VERSION 5.8 ;
BUSBITCHARS "[]" ;
DIVIDERCHAR "/" ;

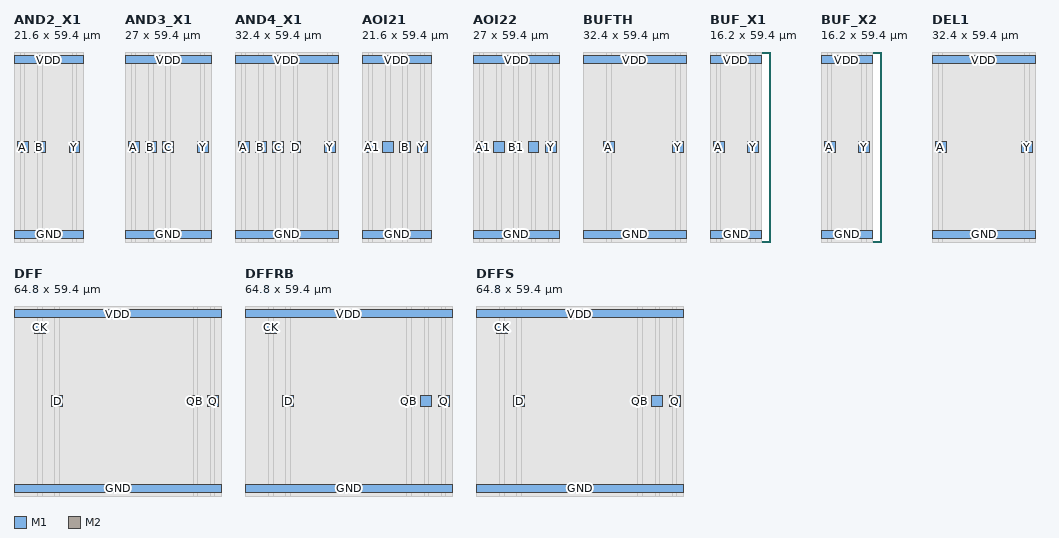
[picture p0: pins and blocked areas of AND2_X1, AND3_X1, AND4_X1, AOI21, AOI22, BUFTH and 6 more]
MACRO AND2_X1
  CLASS CORE ;
  FOREIGN AND2_X1 0 0 ;
  ORIGIN 0 0 ;
  SIZE 21.6 BY 59.4 ;
  SITE TR1UM ;
  SYMMETRY X Y ;
  PIN VDD
    DIRECTION INOUT ;
    USE POWER ;
    PORT
      LAYER M1 ;
        RECT 0 55.7 21.6 58.3 ;
    END
  END VDD
  PIN GND
    DIRECTION INOUT ;
    USE GROUND ;
    PORT
      LAYER M1 ;
        RECT 0 1.1 21.6 3.7 ;
    END
  END GND
  PIN A
    DIRECTION INPUT ;
    USE SIGNAL ;
    PORT
      LAYER M2 ;
        RECT 1 28 4.4 31.4 ;
    END
    PORT
      LAYER M1 ;
        RECT 1 28 4.4 31.4 ;
    END
  END A
  PIN B
    DIRECTION INPUT ;
    USE SIGNAL ;
    PORT
      LAYER M2 ;
        RECT 6.4 28 9.8 31.4 ;
    END
    PORT
      LAYER M1 ;
        RECT 6.4 28 9.8 31.4 ;
    END
  END B
  PIN Y
    DIRECTION OUTPUT ;
    USE SIGNAL ;
    PORT
      LAYER M2 ;
        RECT 17.2 28 20.6 31.4 ;
    END
    PORT
      LAYER M1 ;
        RECT 17.2 28 20.6 31.4 ;
    END
  END Y
  OBS
    LAYER M1 ;
        RECT 0 0 1 59.4 ;
        RECT 1 0 4.4 28 ;
        RECT 1 31.4 4.4 59.4 ;
        RECT 4.4 0 6.4 59.4 ;
        RECT 6.4 0 9.8 28 ;
        RECT 6.4 31.4 9.8 59.4 ;
        RECT 9.8 0 17.2 59.4 ;
        RECT 17.2 0 20.6 28 ;
        RECT 17.2 31.4 20.6 59.4 ;
        RECT 20.6 0 21.6 59.4 ;
    LAYER V1 ;
        RECT 0 0 2 59.4 ;
        RECT 2 0 3.4 29 ;
        RECT 2 30.4 3.4 59.4 ;
        RECT 3.4 0 7.4 59.4 ;
        RECT 7.4 0 8.8 29 ;
        RECT 7.4 30.4 8.8 59.4 ;
        RECT 8.8 0 18.2 59.4 ;
        RECT 18.2 0 19.6 29 ;
        RECT 18.2 30.4 19.6 59.4 ;
        RECT 19.6 0 21.6 59.4 ;
  END
END AND2_X1

MACRO AND3_X1
  CLASS CORE ;
  FOREIGN AND3_X1 0 0 ;
  ORIGIN 0 0 ;
  SIZE 27 BY 59.4 ;
  SITE TR1UM ;
  SYMMETRY X Y ;
  PIN VDD
    DIRECTION INOUT ;
    USE POWER ;
    PORT
      LAYER M1 ;
        RECT 0 55.7 27 58.3 ;
    END
  END VDD
  PIN GND
    DIRECTION INOUT ;
    USE GROUND ;
    PORT
      LAYER M1 ;
        RECT 0 1.1 27 3.7 ;
    END
  END GND
  PIN A
    DIRECTION INPUT ;
    USE SIGNAL ;
    PORT
      LAYER M2 ;
        RECT 1 28 4.4 31.4 ;
    END
    PORT
      LAYER M1 ;
        RECT 1 28 4.4 31.4 ;
    END
  END A
  PIN B
    DIRECTION INPUT ;
    USE SIGNAL ;
    PORT
      LAYER M2 ;
        RECT 6.4 28 9.8 31.4 ;
    END
    PORT
      LAYER M1 ;
        RECT 6.4 28 9.8 31.4 ;
    END
  END B
  PIN C
    DIRECTION INPUT ;
    USE SIGNAL ;
    PORT
      LAYER M2 ;
        RECT 11.8 28 15.2 31.4 ;
    END
    PORT
      LAYER M1 ;
        RECT 11.8 28 15.2 31.4 ;
    END
  END C
  PIN Y
    DIRECTION OUTPUT ;
    USE SIGNAL ;
    PORT
      LAYER M2 ;
        RECT 22.6 28 26 31.4 ;
    END
    PORT
      LAYER M1 ;
        RECT 22.6 28 26 31.4 ;
    END
  END Y
  OBS
    LAYER M1 ;
        RECT 0 0 1 59.4 ;
        RECT 1 0 4.4 28 ;
        RECT 1 31.4 4.4 59.4 ;
        RECT 4.4 0 6.4 59.4 ;
        RECT 6.4 0 9.8 28 ;
        RECT 6.4 31.4 9.8 59.4 ;
        RECT 9.8 0 11.8 59.4 ;
        RECT 11.8 0 15.2 28 ;
        RECT 11.8 31.4 15.2 59.4 ;
        RECT 15.2 0 22.6 59.4 ;
        RECT 22.6 0 26 28 ;
        RECT 22.6 31.4 26 59.4 ;
        RECT 26 0 27 59.4 ;
    LAYER V1 ;
        RECT 0 0 2 59.4 ;
        RECT 2 0 3.4 29 ;
        RECT 2 30.4 3.4 59.4 ;
        RECT 3.4 0 7.4 59.4 ;
        RECT 7.4 0 8.8 29 ;
        RECT 7.4 30.4 8.8 59.4 ;
        RECT 8.8 0 12.8 59.4 ;
        RECT 12.8 0 14.2 29 ;
        RECT 12.8 30.4 14.2 59.4 ;
        RECT 14.2 0 23.6 59.4 ;
        RECT 23.6 0 25 29 ;
        RECT 23.6 30.4 25 59.4 ;
        RECT 25 0 27 59.4 ;
  END
END AND3_X1

MACRO AND4_X1
  CLASS CORE ;
  FOREIGN AND4_X1 0 0 ;
  ORIGIN 0 0 ;
  SIZE 32.4 BY 59.4 ;
  SITE TR1UM ;
  SYMMETRY X Y ;
  PIN VDD
    DIRECTION INOUT ;
    USE POWER ;
    PORT
      LAYER M1 ;
        RECT 0 55.7 32.4 58.3 ;
    END
  END VDD
  PIN GND
    DIRECTION INOUT ;
    USE GROUND ;
    PORT
      LAYER M1 ;
        RECT 0 1.1 32.4 3.7 ;
    END
  END GND
  PIN A
    DIRECTION INPUT ;
    USE SIGNAL ;
    PORT
      LAYER M2 ;
        RECT 1 28 4.4 31.4 ;
    END
    PORT
      LAYER M1 ;
        RECT 1 28 4.4 31.4 ;
    END
  END A
  PIN B
    DIRECTION INPUT ;
    USE SIGNAL ;
    PORT
      LAYER M2 ;
        RECT 6.4 28 9.8 31.4 ;
    END
    PORT
      LAYER M1 ;
        RECT 6.4 28 9.8 31.4 ;
    END
  END B
  PIN C
    DIRECTION INPUT ;
    USE SIGNAL ;
    PORT
      LAYER M2 ;
        RECT 11.8 28 15.2 31.4 ;
    END
    PORT
      LAYER M1 ;
        RECT 11.8 28 15.2 31.4 ;
    END
  END C
  PIN D
    DIRECTION INPUT ;
    USE SIGNAL ;
    PORT
      LAYER M2 ;
        RECT 17.2 28 20.6 31.4 ;
    END
    PORT
      LAYER M1 ;
        RECT 17.2 28 20.6 31.4 ;
    END
  END D
  PIN Y
    DIRECTION OUTPUT ;
    USE SIGNAL ;
    PORT
      LAYER M2 ;
        RECT 28 28 31.4 31.4 ;
    END
    PORT
      LAYER M1 ;
        RECT 28 28 31.4 31.4 ;
    END
  END Y
  OBS
    LAYER M1 ;
        RECT 0 0 1 59.4 ;
        RECT 1 0 4.4 28 ;
        RECT 1 31.4 4.4 59.4 ;
        RECT 4.4 0 6.4 59.4 ;
        RECT 6.4 0 9.8 28 ;
        RECT 6.4 31.4 9.8 59.4 ;
        RECT 9.8 0 11.8 59.4 ;
        RECT 11.8 0 15.2 28 ;
        RECT 11.8 31.4 15.2 59.4 ;
        RECT 15.2 0 17.2 59.4 ;
        RECT 17.2 0 20.6 28 ;
        RECT 17.2 31.4 20.6 59.4 ;
        RECT 20.6 0 28 59.4 ;
        RECT 28 0 31.4 28 ;
        RECT 28 31.4 31.4 59.4 ;
        RECT 31.4 0 32.4 59.4 ;
    LAYER V1 ;
        RECT 0 0 2 59.4 ;
        RECT 2 0 3.4 29 ;
        RECT 2 30.4 3.4 59.4 ;
        RECT 3.4 0 7.4 59.4 ;
        RECT 7.4 0 8.8 29 ;
        RECT 7.4 30.4 8.8 59.4 ;
        RECT 8.8 0 12.8 59.4 ;
        RECT 12.8 0 14.2 29 ;
        RECT 12.8 30.4 14.2 59.4 ;
        RECT 14.2 0 18.2 59.4 ;
        RECT 18.2 0 19.6 29 ;
        RECT 18.2 30.4 19.6 59.4 ;
        RECT 19.6 0 29 59.4 ;
        RECT 29 0 30.4 29 ;
        RECT 29 30.4 30.4 59.4 ;
        RECT 30.4 0 32.4 59.4 ;
  END
END AND4_X1

MACRO AOI21
  CLASS CORE ;
  FOREIGN AOI21 0 0 ;
  ORIGIN 0 0 ;
  SIZE 21.6 BY 59.4 ;
  SITE TR1UM ;
  SYMMETRY X Y ;
  PIN VDD
    DIRECTION INOUT ;
    USE POWER ;
    PORT
      LAYER M1 ;
        RECT 0 55.7 21.6 58.3 ;
    END
  END VDD
  PIN GND
    DIRECTION INOUT ;
    USE GROUND ;
    PORT
      LAYER M1 ;
        RECT 0 1.1 21.6 3.7 ;
    END
  END GND
  PIN A1
    DIRECTION INPUT ;
    USE SIGNAL ;
    PORT
      LAYER M2 ;
        RECT 1 28 4.4 31.4 ;
    END
    PORT
      LAYER M1 ;
        RECT 1 28 4.4 31.4 ;
    END
  END A1
  PIN A2
    DIRECTION INPUT ;
    USE SIGNAL ;
    PORT
      LAYER M2 ;
        RECT 6.4 28 9.8 31.4 ;
    END
    PORT
      LAYER M1 ;
        RECT 6.4 28 9.8 31.4 ;
    END
  END A2
  PIN B
    DIRECTION INPUT ;
    USE SIGNAL ;
    PORT
      LAYER M2 ;
        RECT 11.8 28 15.2 31.4 ;
    END
    PORT
      LAYER M1 ;
        RECT 11.8 28 15.2 31.4 ;
    END
  END B
  PIN Y
    DIRECTION OUTPUT ;
    USE SIGNAL ;
    PORT
      LAYER M2 ;
        RECT 17.2 28 20.6 31.4 ;
    END
    PORT
      LAYER M1 ;
        RECT 17.2 28 20.6 31.4 ;
    END
  END Y
  OBS
    LAYER M1 ;
        RECT 0 0 1 59.4 ;
        RECT 1 0 4.4 28 ;
        RECT 1 31.4 4.4 59.4 ;
        RECT 4.4 0 6.4 59.4 ;
        RECT 6.4 0 9.8 28 ;
        RECT 6.4 31.4 9.8 59.4 ;
        RECT 9.8 0 11.8 59.4 ;
        RECT 11.8 0 15.2 28 ;
        RECT 11.8 31.4 15.2 59.4 ;
        RECT 15.2 0 17.2 59.4 ;
        RECT 17.2 0 20.6 28 ;
        RECT 17.2 31.4 20.6 59.4 ;
        RECT 20.6 0 21.6 59.4 ;
    LAYER V1 ;
        RECT 0 0 2 59.4 ;
        RECT 2 0 3.4 29 ;
        RECT 2 30.4 3.4 59.4 ;
        RECT 3.4 0 7.4 59.4 ;
        RECT 7.4 0 8.8 29 ;
        RECT 7.4 30.4 8.8 59.4 ;
        RECT 8.8 0 12.8 59.4 ;
        RECT 12.8 0 14.2 29 ;
        RECT 12.8 30.4 14.2 59.4 ;
        RECT 14.2 0 18.2 59.4 ;
        RECT 18.2 0 19.6 29 ;
        RECT 18.2 30.4 19.6 59.4 ;
        RECT 19.6 0 21.6 59.4 ;
  END
END AOI21

MACRO AOI22
  CLASS CORE ;
  FOREIGN AOI22 0 0 ;
  ORIGIN 0 0 ;
  SIZE 27 BY 59.4 ;
  SITE TR1UM ;
  SYMMETRY X Y ;
  PIN VDD
    DIRECTION INOUT ;
    USE POWER ;
    PORT
      LAYER M1 ;
        RECT 0 55.7 27 58.3 ;
    END
  END VDD
  PIN GND
    DIRECTION INOUT ;
    USE GROUND ;
    PORT
      LAYER M1 ;
        RECT 0 1.1 27 3.7 ;
    END
  END GND
  PIN A1
    DIRECTION INPUT ;
    USE SIGNAL ;
    PORT
      LAYER M2 ;
        RECT 1 28 4.4 31.4 ;
    END
    PORT
      LAYER M1 ;
        RECT 1 28 4.4 31.4 ;
    END
  END A1
  PIN A2
    DIRECTION INPUT ;
    USE SIGNAL ;
    PORT
      LAYER M2 ;
        RECT 6.4 28 9.8 31.4 ;
    END
    PORT
      LAYER M1 ;
        RECT 6.4 28 9.8 31.4 ;
    END
  END A2
  PIN B1
    DIRECTION INPUT ;
    USE SIGNAL ;
    PORT
      LAYER M2 ;
        RECT 11.8 28 15.2 31.4 ;
    END
    PORT
      LAYER M1 ;
        RECT 11.8 28 15.2 31.4 ;
    END
  END B1
  PIN B2
    DIRECTION INPUT ;
    USE SIGNAL ;
    PORT
      LAYER M2 ;
        RECT 17.2 28 20.6 31.4 ;
    END
    PORT
      LAYER M1 ;
        RECT 17.2 28 20.6 31.4 ;
    END
  END B2
  PIN Y
    DIRECTION OUTPUT ;
    USE SIGNAL ;
    PORT
      LAYER M2 ;
        RECT 22.6 28 26 31.4 ;
    END
    PORT
      LAYER M1 ;
        RECT 22.6 28 26 31.4 ;
    END
  END Y
  OBS
    LAYER M1 ;
        RECT 0 0 1 59.4 ;
        RECT 1 0 4.4 28 ;
        RECT 1 31.4 4.4 59.4 ;
        RECT 4.4 0 6.4 59.4 ;
        RECT 6.4 0 9.8 28 ;
        RECT 6.4 31.4 9.8 59.4 ;
        RECT 9.8 0 11.8 59.4 ;
        RECT 11.8 0 15.2 28 ;
        RECT 11.8 31.4 15.2 59.4 ;
        RECT 15.2 0 17.2 59.4 ;
        RECT 17.2 0 20.6 28 ;
        RECT 17.2 31.4 20.6 59.4 ;
        RECT 20.6 0 22.6 59.4 ;
        RECT 22.6 0 26 28 ;
        RECT 22.6 31.4 26 59.4 ;
        RECT 26 0 27 59.4 ;
    LAYER V1 ;
        RECT 0 0 2 59.4 ;
        RECT 2 0 3.4 29 ;
        RECT 2 30.4 3.4 59.4 ;
        RECT 3.4 0 7.4 59.4 ;
        RECT 7.4 0 8.8 29 ;
        RECT 7.4 30.4 8.8 59.4 ;
        RECT 8.8 0 12.8 59.4 ;
        RECT 12.8 0 14.2 29 ;
        RECT 12.8 30.4 14.2 59.4 ;
        RECT 14.2 0 18.2 59.4 ;
        RECT 18.2 0 19.6 29 ;
        RECT 18.2 30.4 19.6 59.4 ;
        RECT 19.6 0 23.6 59.4 ;
        RECT 23.6 0 25 29 ;
        RECT 23.6 30.4 25 59.4 ;
        RECT 25 0 27 59.4 ;
  END
END AOI22

MACRO BUFTH
  CLASS CORE ;
  FOREIGN BUFTH 0 0 ;
  ORIGIN 0 0 ;
  SIZE 32.4 BY 59.4 ;
  SITE TR1UM ;
  SYMMETRY X Y ;
  PIN VDD
    DIRECTION INOUT ;
    USE POWER ;
    PORT
      LAYER M1 ;
        RECT 0 55.7 32.4 58.3 ;
    END
  END VDD
  PIN GND
    DIRECTION INOUT ;
    USE GROUND ;
    PORT
      LAYER M1 ;
        RECT 0 1.1 32.4 3.7 ;
    END
  END GND
  PIN A
    DIRECTION INPUT ;
    USE SIGNAL ;
    PORT
      LAYER M2 ;
        RECT 6.4 28 9.8 31.4 ;
    END
    PORT
      LAYER M1 ;
        RECT 6.4 28 9.8 31.4 ;
    END
  END A
  PIN Y
    DIRECTION OUTPUT ;
    USE SIGNAL ;
    PORT
      LAYER M2 ;
        RECT 28 28 31.4 31.4 ;
    END
    PORT
      LAYER M1 ;
        RECT 28 28 31.4 31.4 ;
    END
  END Y
  OBS
    LAYER M1 ;
        RECT 0 0 6.4 59.4 ;
        RECT 6.4 0 9.8 28 ;
        RECT 6.4 31.4 9.8 59.4 ;
        RECT 9.8 0 28 59.4 ;
        RECT 28 0 31.4 28 ;
        RECT 28 31.4 31.4 59.4 ;
        RECT 31.4 0 32.4 59.4 ;
    LAYER V1 ;
        RECT 0 0 7.4 59.4 ;
        RECT 7.4 0 8.8 29 ;
        RECT 7.4 30.4 8.8 59.4 ;
        RECT 8.8 0 29 59.4 ;
        RECT 29 0 30.4 29 ;
        RECT 29 30.4 30.4 59.4 ;
        RECT 30.4 0 32.4 59.4 ;
  END
END BUFTH

MACRO BUF_X1
  CLASS CORE ;
  FOREIGN BUF_X1 0 0 ;
  ORIGIN 0 0 ;
  SIZE 16.2 BY 59.4 ;
  SITE TR1UM ;
  SYMMETRY X Y ;
  PIN VDD
    DIRECTION INOUT ;
    USE POWER ;
    PORT
      LAYER M1 ;
        RECT 0 55.7 16.2 58.3 ;
    END
  END VDD
  PIN GND
    DIRECTION INOUT ;
    USE GROUND ;
    PORT
      LAYER M1 ;
        RECT 0 1.1 16.2 3.7 ;
    END
  END GND
  PIN A
    DIRECTION INPUT ;
    USE SIGNAL ;
    PORT
      LAYER M2 ;
        RECT 1 28 4.4 31.4 ;
    END
    PORT
      LAYER M1 ;
        RECT 1 28 4.4 31.4 ;
    END
  END A
  PIN Y
    DIRECTION OUTPUT ;
    USE SIGNAL ;
    PORT
      LAYER M2 ;
        RECT 11.8 28 15.2 31.4 ;
    END
    PORT
      LAYER M1 ;
        RECT 11.8 28 15.2 31.4 ;
    END
  END Y
  OBS
    LAYER M1 ;
        RECT 0 0 1 59.4 ;
        RECT 1 0 4.4 28 ;
        RECT 1 31.4 4.4 59.4 ;
        RECT 4.4 0 11.8 59.4 ;
        RECT 11.8 0 15.2 28 ;
        RECT 11.8 31.4 15.2 59.4 ;
        RECT 15.2 0 16.2 59.4 ;
    LAYER V1 ;
        RECT 0 0 2 59.4 ;
        RECT 2 0 3.4 29 ;
        RECT 2 30.4 3.4 59.4 ;
        RECT 3.4 0 12.8 59.4 ;
        RECT 12.8 0 14.2 29 ;
        RECT 12.8 30.4 14.2 59.4 ;
        RECT 14.2 0 16.2 59.4 ;
  END
END BUF_X1

MACRO BUF_X2
  CLASS CORE ;
  FOREIGN BUF_X2 0 0 ;
  ORIGIN 0 0 ;
  SIZE 16.2 BY 59.4 ;
  SITE TR1UM ;
  SYMMETRY X Y ;
  PIN VDD
    DIRECTION INOUT ;
    USE POWER ;
    PORT
      LAYER M1 ;
        RECT 0 55.7 16.2 58.3 ;
    END
  END VDD
  PIN GND
    DIRECTION INOUT ;
    USE GROUND ;
    PORT
      LAYER M1 ;
        RECT 0 1.1 16.2 3.7 ;
    END
  END GND
  PIN A
    DIRECTION INPUT ;
    USE SIGNAL ;
    PORT
      LAYER M2 ;
        RECT 1 28 4.4 31.4 ;
    END
    PORT
      LAYER M1 ;
        RECT 1 28 4.4 31.4 ;
    END
  END A
  PIN Y
    DIRECTION OUTPUT ;
    USE SIGNAL ;
    PORT
      LAYER M2 ;
        RECT 11.8 28 15.2 31.4 ;
    END
    PORT
      LAYER M1 ;
        RECT 11.8 28 15.2 31.4 ;
    END
  END Y
  OBS
    LAYER M1 ;
        RECT 0 0 1 59.4 ;
        RECT 1 0 4.4 28 ;
        RECT 1 31.4 4.4 59.4 ;
        RECT 4.4 0 11.8 59.4 ;
        RECT 11.8 0 15.2 28 ;
        RECT 11.8 31.4 15.2 59.4 ;
        RECT 15.2 0 16.2 59.4 ;
    LAYER V1 ;
        RECT 0 0 2 59.4 ;
        RECT 2 0 3.4 29 ;
        RECT 2 30.4 3.4 59.4 ;
        RECT 3.4 0 12.8 59.4 ;
        RECT 12.8 0 14.2 29 ;
        RECT 12.8 30.4 14.2 59.4 ;
        RECT 14.2 0 16.2 59.4 ;
  END
END BUF_X2

MACRO DEL1
  CLASS CORE ;
  FOREIGN DEL1 0 0 ;
  ORIGIN 0 0 ;
  SIZE 32.4 BY 59.4 ;
  SITE TR1UM ;
  SYMMETRY X Y ;
  PIN VDD
    DIRECTION INOUT ;
    USE POWER ;
    PORT
      LAYER M1 ;
        RECT 0 55.7 32.4 58.3 ;
    END
  END VDD
  PIN GND
    DIRECTION INOUT ;
    USE GROUND ;
    PORT
      LAYER M1 ;
        RECT 0 1.1 32.4 3.7 ;
    END
  END GND
  PIN A
    DIRECTION INPUT ;
    USE SIGNAL ;
    PORT
      LAYER M2 ;
        RECT 1 28 4.4 31.4 ;
    END
    PORT
      LAYER M1 ;
        RECT 1 28 4.4 31.4 ;
    END
  END A
  PIN Y
    DIRECTION OUTPUT ;
    USE SIGNAL ;
    PORT
      LAYER M2 ;
        RECT 28 28 31.4 31.4 ;
    END
    PORT
      LAYER M1 ;
        RECT 28 28 31.4 31.4 ;
    END
  END Y
  OBS
    LAYER M1 ;
        RECT 0 0 1 59.4 ;
        RECT 1 0 4.4 28 ;
        RECT 1 31.4 4.4 59.4 ;
        RECT 4.4 0 28 59.4 ;
        RECT 28 0 31.4 28 ;
        RECT 28 31.4 31.4 59.4 ;
        RECT 31.4 0 32.4 59.4 ;
    LAYER V1 ;
        RECT 0 0 2 59.4 ;
        RECT 2 0 3.4 29 ;
        RECT 2 30.4 3.4 59.4 ;
        RECT 3.4 0 29 59.4 ;
        RECT 29 0 30.4 29 ;
        RECT 29 30.4 30.4 59.4 ;
        RECT 30.4 0 32.4 59.4 ;
  END
END DEL1

MACRO DFF
  CLASS CORE ;
  FOREIGN DFF 0 0 ;
  ORIGIN 0 0 ;
  SIZE 64.8 BY 59.4 ;
  SITE TR1UM ;
  SYMMETRY X Y ;
  PIN VDD
    DIRECTION INOUT ;
    USE POWER ;
    PORT
      LAYER M1 ;
        RECT 0 55.7 64.8 58.3 ;
    END
  END VDD
  PIN GND
    DIRECTION INOUT ;
    USE GROUND ;
    PORT
      LAYER M1 ;
        RECT 0 1.1 64.8 3.7 ;
    END
  END GND
  PIN CK
    DIRECTION INPUT ;
    USE SIGNAL ;
    PORT
      LAYER M2 ;
        RECT 6.4 50.9 9.8 54.3 ;
    END
    PORT
      LAYER M1 ;
        RECT 6.4 50.9 9.8 54.3 ;
    END
  END CK
  PIN D
    DIRECTION INPUT ;
    USE SIGNAL ;
    PORT
      LAYER M2 ;
        RECT 11.8 27.9 15.2 31.3 ;
    END
    PORT
      LAYER M1 ;
        RECT 11.8 27.9 15.2 31.3 ;
    END
  END D
  PIN Q
    DIRECTION OUTPUT ;
    USE SIGNAL ;
    PORT
      LAYER M2 ;
        RECT 60.4 27.9 63.8 31.3 ;
    END
    PORT
      LAYER M1 ;
        RECT 60.4 27.9 63.8 31.3 ;
    END
  END Q
  PIN QB
    DIRECTION OUTPUT ;
    USE SIGNAL ;
    PORT
      LAYER M2 ;
        RECT 55 27.9 58.4 31.3 ;
    END
    PORT
      LAYER M1 ;
        RECT 55 27.9 58.4 31.3 ;
    END
  END QB
  OBS
    LAYER M1 ;
        RECT 0 0 6.4 59.4 ;
        RECT 6.4 0 9.8 50.9 ;
        RECT 6.4 54.3 9.8 59.4 ;
        RECT 9.8 0 11.8 59.4 ;
        RECT 11.8 0 15.2 27.9 ;
        RECT 11.8 31.3 15.2 59.4 ;
        RECT 15.2 0 55 59.4 ;
        RECT 55 0 58.4 27.9 ;
        RECT 55 31.3 58.4 59.4 ;
        RECT 58.4 0 60.4 59.4 ;
        RECT 60.4 0 63.8 27.9 ;
        RECT 60.4 31.3 63.8 59.4 ;
        RECT 63.8 0 64.8 59.4 ;
    LAYER V1 ;
        RECT 0 0 7.4 59.4 ;
        RECT 7.4 0 8.8 51.9 ;
        RECT 7.4 53.3 8.8 59.4 ;
        RECT 8.8 0 12.8 59.4 ;
        RECT 12.8 0 14.2 28.9 ;
        RECT 12.8 30.3 14.2 59.4 ;
        RECT 14.2 0 56 59.4 ;
        RECT 56 0 57.4 28.9 ;
        RECT 56 30.3 57.4 59.4 ;
        RECT 57.4 0 61.4 59.4 ;
        RECT 61.4 0 62.8 28.9 ;
        RECT 61.4 30.3 62.8 59.4 ;
        RECT 62.8 0 64.8 59.4 ;
  END
END DFF

MACRO DFFRB
  CLASS CORE ;
  FOREIGN DFFRB 0 0 ;
  ORIGIN 0 0 ;
  SIZE 64.8 BY 59.4 ;
  SITE TR1UM ;
  SYMMETRY X Y ;
  PIN VDD
    DIRECTION INOUT ;
    USE POWER ;
    PORT
      LAYER M1 ;
        RECT 0 55.7 64.8 58.3 ;
    END
  END VDD
  PIN GND
    DIRECTION INOUT ;
    USE GROUND ;
    PORT
      LAYER M1 ;
        RECT 0 1.1 64.8 3.7 ;
    END
  END GND
  PIN CK
    DIRECTION INPUT ;
    USE SIGNAL ;
    PORT
      LAYER M2 ;
        RECT 6.4 50.9 9.8 54.3 ;
    END
    PORT
      LAYER M1 ;
        RECT 6.4 50.9 9.8 54.3 ;
    END
  END CK
  PIN D
    DIRECTION INPUT ;
    USE SIGNAL ;
    PORT
      LAYER M2 ;
        RECT 11.8 27.9 15.2 31.3 ;
    END
    PORT
      LAYER M1 ;
        RECT 11.8 27.9 15.2 31.3 ;
    END
  END D
  PIN Q
    DIRECTION OUTPUT ;
    USE SIGNAL ;
    PORT
      LAYER M2 ;
        RECT 60.4 27.9 63.8 31.3 ;
    END
    PORT
      LAYER M1 ;
        RECT 60.4 27.9 63.8 31.3 ;
    END
  END Q
  PIN QB
    DIRECTION OUTPUT ;
    USE SIGNAL ;
    PORT
      LAYER M2 ;
        RECT 49.6 27.9 53 31.3 ;
        RECT 49.6 27.9 53 31.3 ;
    END
    PORT
      LAYER M1 ;
        RECT 49.6 27.9 53 31.3 ;
        RECT 49.6 27.9 53 31.3 ;
    END
  END QB
  PIN RSTB
    DIRECTION INPUT ;
    USE SIGNAL ;
    PORT
      LAYER M2 ;
        RECT 55 27.9 58.4 31.3 ;
    END
    PORT
      LAYER M1 ;
        RECT 55 27.9 58.4 31.3 ;
    END
  END RSTB
  OBS
    LAYER M1 ;
        RECT 0 0 6.4 59.4 ;
        RECT 6.4 0 9.8 50.9 ;
        RECT 6.4 54.3 9.8 59.4 ;
        RECT 9.8 0 11.8 59.4 ;
        RECT 11.8 0 15.2 27.9 ;
        RECT 11.8 31.3 15.2 59.4 ;
        RECT 15.2 0 49.6 59.4 ;
        RECT 49.6 0 53 27.9 ;
        RECT 49.6 31.3 53 59.4 ;
        RECT 53 0 55 59.4 ;
        RECT 55 0 58.4 27.9 ;
        RECT 55 31.3 58.4 59.4 ;
        RECT 58.4 0 60.4 59.4 ;
        RECT 60.4 0 63.8 27.9 ;
        RECT 60.4 31.3 63.8 59.4 ;
        RECT 63.8 0 64.8 59.4 ;
    LAYER V1 ;
        RECT 0 0 7.4 59.4 ;
        RECT 7.4 0 8.8 51.9 ;
        RECT 7.4 53.3 8.8 59.4 ;
        RECT 8.8 0 12.8 59.4 ;
        RECT 12.8 0 14.2 28.9 ;
        RECT 12.8 30.3 14.2 59.4 ;
        RECT 14.2 0 50.6 59.4 ;
        RECT 50.6 0 52 28.9 ;
        RECT 50.6 30.3 52 59.4 ;
        RECT 52 0 56 59.4 ;
        RECT 56 0 57.4 28.9 ;
        RECT 56 30.3 57.4 59.4 ;
        RECT 57.4 0 61.4 59.4 ;
        RECT 61.4 0 62.8 28.9 ;
        RECT 61.4 30.3 62.8 59.4 ;
        RECT 62.8 0 64.8 59.4 ;
  END
END DFFRB

MACRO DFFS
  CLASS CORE ;
  FOREIGN DFFS 0 0 ;
  ORIGIN 0 0 ;
  SIZE 64.8 BY 59.4 ;
  SITE TR1UM ;
  SYMMETRY X Y ;
  PIN VDD
    DIRECTION INOUT ;
    USE POWER ;
    PORT
      LAYER M1 ;
        RECT 0 55.7 64.8 58.3 ;
    END
  END VDD
  PIN GND
    DIRECTION INOUT ;
    USE GROUND ;
    PORT
      LAYER M1 ;
        RECT 0 1.1 64.8 3.7 ;
    END
  END GND
  PIN CK
    DIRECTION INPUT ;
    USE SIGNAL ;
    PORT
      LAYER M2 ;
        RECT 6.4 50.9 9.8 54.3 ;
    END
    PORT
      LAYER M1 ;
        RECT 6.4 50.9 9.8 54.3 ;
    END
  END CK
  PIN D
    DIRECTION INPUT ;
    USE SIGNAL ;
    PORT
      LAYER M2 ;
        RECT 11.8 27.9 15.2 31.3 ;
    END
    PORT
      LAYER M1 ;
        RECT 11.8 27.9 15.2 31.3 ;
    END
  END D
  PIN Q
    DIRECTION OUTPUT ;
    USE SIGNAL ;
    PORT
      LAYER M2 ;
        RECT 60.4 27.9 63.8 31.3 ;
    END
    PORT
      LAYER M1 ;
        RECT 60.4 27.9 63.8 31.3 ;
    END
  END Q
  PIN QB
    DIRECTION OUTPUT ;
    USE SIGNAL ;
    PORT
      LAYER M2 ;
        RECT 49.6 27.9 53 31.3 ;
        RECT 49.6 27.9 53 31.3 ;
    END
    PORT
      LAYER M1 ;
        RECT 49.6 27.9 53 31.3 ;
        RECT 49.6 27.9 53 31.3 ;
    END
  END QB
  PIN SET
    DIRECTION INPUT ;
    USE SIGNAL ;
    PORT
      LAYER M2 ;
        RECT 55 27.9 58.4 31.3 ;
    END
    PORT
      LAYER M1 ;
        RECT 55 27.9 58.4 31.3 ;
    END
  END SET
  OBS
    LAYER M1 ;
        RECT 0 0 6.4 59.4 ;
        RECT 6.4 0 9.8 50.9 ;
        RECT 6.4 54.3 9.8 59.4 ;
        RECT 9.8 0 11.8 59.4 ;
        RECT 11.8 0 15.2 27.9 ;
        RECT 11.8 31.3 15.2 59.4 ;
        RECT 15.2 0 49.6 59.4 ;
        RECT 49.6 0 53 27.9 ;
        RECT 49.6 31.3 53 59.4 ;
        RECT 53 0 55 59.4 ;
        RECT 55 0 58.4 27.9 ;
        RECT 55 31.3 58.4 59.4 ;
        RECT 58.4 0 60.4 59.4 ;
        RECT 60.4 0 63.8 27.9 ;
        RECT 60.4 31.3 63.8 59.4 ;
        RECT 63.8 0 64.8 59.4 ;
    LAYER V1 ;
        RECT 0 0 7.4 59.4 ;
        RECT 7.4 0 8.8 51.9 ;
        RECT 7.4 53.3 8.8 59.4 ;
        RECT 8.8 0 12.8 59.4 ;
        RECT 12.8 0 14.2 28.9 ;
        RECT 12.8 30.3 14.2 59.4 ;
        RECT 14.2 0 50.6 59.4 ;
        RECT 50.6 0 52 28.9 ;
        RECT 50.6 30.3 52 59.4 ;
        RECT 52 0 56 59.4 ;
        RECT 56 0 57.4 28.9 ;
        RECT 56 30.3 57.4 59.4 ;
        RECT 57.4 0 61.4 59.4 ;
        RECT 61.4 0 62.8 28.9 ;
        RECT 61.4 30.3 62.8 59.4 ;
        RECT 62.8 0 64.8 59.4 ;
  END
END DFFS

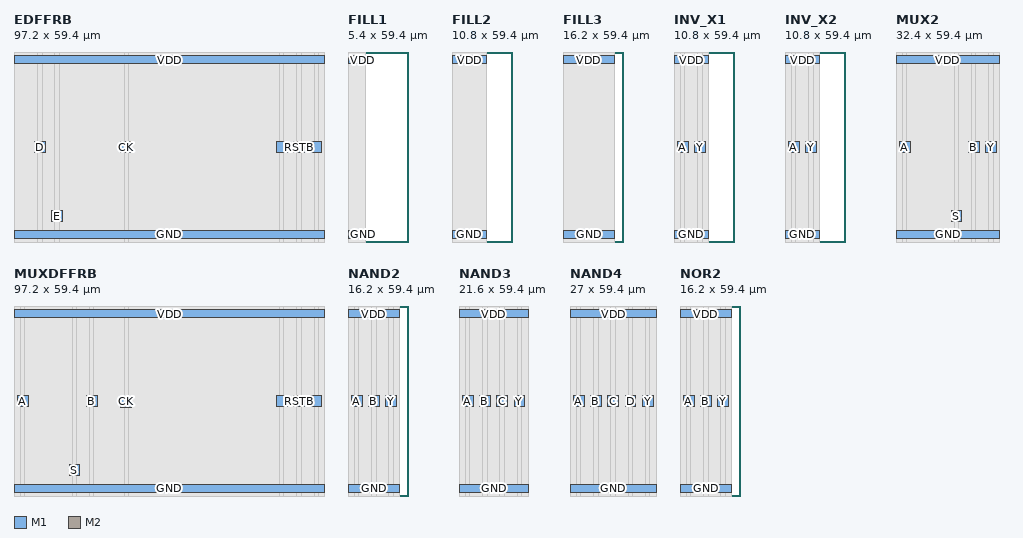
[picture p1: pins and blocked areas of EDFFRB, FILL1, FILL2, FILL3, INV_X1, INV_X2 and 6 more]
MACRO EDFFRB
  CLASS CORE ;
  FOREIGN EDFFRB 0 0 ;
  ORIGIN 0 0 ;
  SIZE 97.2 BY 59.4 ;
  SITE TR1UM ;
  SYMMETRY X Y ;
  PIN VDD
    DIRECTION INOUT ;
    USE POWER ;
    PORT
      LAYER M1 ;
        RECT 0 55.7 97.2 58.3 ;
    END
  END VDD
  PIN GND
    DIRECTION INOUT ;
    USE GROUND ;
    PORT
      LAYER M1 ;
        RECT 0 1.1 97.2 3.7 ;
    END
  END GND
  PIN CK
    DIRECTION INPUT ;
    USE SIGNAL ;
    PORT
      LAYER M2 ;
        RECT 33.4 27.9 36.8 31.3 ;
    END
    PORT
      LAYER M1 ;
        RECT 33.4 27.9 36.8 31.3 ;
    END
  END CK
  PIN D
    DIRECTION INPUT ;
    USE SIGNAL ;
    PORT
      LAYER M2 ;
        RECT 6.4 27.9 9.8 31.3 ;
    END
    PORT
      LAYER M1 ;
        RECT 6.4 27.9 9.8 31.3 ;
    END
  END D
  PIN E
    DIRECTION INPUT ;
    USE SIGNAL ;
    PORT
      LAYER M2 ;
        RECT 11.8 6.3 15.2 9.7 ;
    END
    PORT
      LAYER M1 ;
        RECT 11.8 6.3 15.2 9.7 ;
    END
  END E
  PIN Q
    DIRECTION OUTPUT ;
    USE SIGNAL ;
    PORT
      LAYER M2 ;
        RECT 92.8 27.9 96.2 31.3 ;
    END
    PORT
      LAYER M1 ;
        RECT 92.8 27.9 96.2 31.3 ;
    END
  END Q
  PIN QB
    DIRECTION OUTPUT ;
    USE SIGNAL ;
    PORT
      LAYER M2 ;
        RECT 82 27.9 85.4 31.3 ;
        RECT 82 27.9 85.4 31.3 ;
    END
    PORT
      LAYER M1 ;
        RECT 82 27.9 85.4 31.3 ;
        RECT 82 27.9 85.4 31.3 ;
    END
  END QB
  PIN RSTB
    DIRECTION INPUT ;
    USE SIGNAL ;
    PORT
      LAYER M2 ;
        RECT 87.4 27.9 90.8 31.3 ;
    END
    PORT
      LAYER M1 ;
        RECT 87.4 27.9 90.8 31.3 ;
    END
  END RSTB
  OBS
    LAYER M1 ;
        RECT 0 0 6.4 59.4 ;
        RECT 6.4 0 9.8 27.9 ;
        RECT 6.4 31.3 9.8 59.4 ;
        RECT 9.8 0 11.8 59.4 ;
        RECT 11.8 0 15.2 6.3 ;
        RECT 11.8 9.7 15.2 59.4 ;
        RECT 15.2 0 33.4 59.4 ;
        RECT 33.4 0 36.8 27.9 ;
        RECT 33.4 31.3 36.8 59.4 ;
        RECT 36.8 0 82 59.4 ;
        RECT 82 0 85.4 27.9 ;
        RECT 82 31.3 85.4 59.4 ;
        RECT 85.4 0 87.4 59.4 ;
        RECT 87.4 0 90.8 27.9 ;
        RECT 87.4 31.3 90.8 59.4 ;
        RECT 90.8 0 92.8 59.4 ;
        RECT 92.8 0 96.2 27.9 ;
        RECT 92.8 31.3 96.2 59.4 ;
        RECT 96.2 0 97.2 59.4 ;
    LAYER V1 ;
        RECT 0 0 7.4 59.4 ;
        RECT 7.4 0 8.8 28.9 ;
        RECT 7.4 30.3 8.8 59.4 ;
        RECT 8.8 0 12.8 59.4 ;
        RECT 12.8 0 14.2 7.3 ;
        RECT 12.8 8.7 14.2 59.4 ;
        RECT 14.2 0 34.4 59.4 ;
        RECT 34.4 0 35.8 28.9 ;
        RECT 34.4 30.3 35.8 59.4 ;
        RECT 35.8 0 83 59.4 ;
        RECT 83 0 84.4 28.9 ;
        RECT 83 30.3 84.4 59.4 ;
        RECT 84.4 0 88.4 59.4 ;
        RECT 88.4 0 89.8 28.9 ;
        RECT 88.4 30.3 89.8 59.4 ;
        RECT 89.8 0 93.8 59.4 ;
        RECT 93.8 0 95.2 28.9 ;
        RECT 93.8 30.3 95.2 59.4 ;
        RECT 95.2 0 97.2 59.4 ;
  END
END EDFFRB

MACRO FILL1
  CLASS CORE SPACER ;
  FOREIGN FILL1 0 0 ;
  ORIGIN 0 0 ;
  SIZE 5.4 BY 59.4 ;
  SITE TR1UM ;
  SYMMETRY X Y ;
  PIN VDD
    DIRECTION INOUT ;
    USE POWER ;
    PORT
      LAYER M1 ;
        RECT 0 55.7 5.4 58.3 ;
    END
  END VDD
  PIN GND
    DIRECTION INOUT ;
    USE GROUND ;
    PORT
      LAYER M1 ;
        RECT 0 1.1 5.4 3.7 ;
    END
  END GND
  OBS
    LAYER M1 ;
        RECT 0 0 5.4 59.4 ;
    LAYER V1 ;
        RECT 0 0 5.4 59.4 ;
  END
END FILL1

MACRO FILL2
  CLASS CORE SPACER ;
  FOREIGN FILL2 0 0 ;
  ORIGIN 0 0 ;
  SIZE 10.8 BY 59.4 ;
  SITE TR1UM ;
  SYMMETRY X Y ;
  PIN VDD
    DIRECTION INOUT ;
    USE POWER ;
    PORT
      LAYER M1 ;
        RECT 0 55.7 10.8 58.3 ;
    END
  END VDD
  PIN GND
    DIRECTION INOUT ;
    USE GROUND ;
    PORT
      LAYER M1 ;
        RECT 0 1.1 10.8 3.7 ;
    END
  END GND
  OBS
    LAYER M1 ;
        RECT 0 0 10.8 59.4 ;
    LAYER V1 ;
        RECT 0 0 10.8 59.4 ;
  END
END FILL2

MACRO FILL3
  CLASS CORE SPACER ;
  FOREIGN FILL3 0 0 ;
  ORIGIN 0 0 ;
  SIZE 16.2 BY 59.4 ;
  SITE TR1UM ;
  SYMMETRY X Y ;
  PIN VDD
    DIRECTION INOUT ;
    USE POWER ;
    PORT
      LAYER M1 ;
        RECT 0 55.7 16.2 58.3 ;
    END
  END VDD
  PIN GND
    DIRECTION INOUT ;
    USE GROUND ;
    PORT
      LAYER M1 ;
        RECT 0 1.1 16.2 3.7 ;
    END
  END GND
  OBS
    LAYER M1 ;
        RECT 0 0 16.2 59.4 ;
    LAYER V1 ;
        RECT 0 0 16.2 59.4 ;
  END
END FILL3

MACRO INV_X1
  CLASS CORE ;
  FOREIGN INV_X1 0 0 ;
  ORIGIN 0 0 ;
  SIZE 10.8 BY 59.4 ;
  SITE TR1UM ;
  SYMMETRY X Y ;
  PIN VDD
    DIRECTION INOUT ;
    USE POWER ;
    PORT
      LAYER M1 ;
        RECT 0 55.7 10.8 58.3 ;
    END
  END VDD
  PIN GND
    DIRECTION INOUT ;
    USE GROUND ;
    PORT
      LAYER M1 ;
        RECT 0 1.1 10.8 3.7 ;
    END
  END GND
  PIN A
    DIRECTION INPUT ;
    USE SIGNAL ;
    PORT
      LAYER M2 ;
        RECT 1 28 4.4 31.4 ;
    END
    PORT
      LAYER M1 ;
        RECT 1 28 4.4 31.4 ;
    END
  END A
  PIN Y
    DIRECTION OUTPUT ;
    USE SIGNAL ;
    PORT
      LAYER M2 ;
        RECT 6.4 28 9.8 31.4 ;
    END
    PORT
      LAYER M1 ;
        RECT 6.4 28 9.8 31.4 ;
    END
  END Y
  OBS
    LAYER M1 ;
        RECT 0 0 1 59.4 ;
        RECT 1 0 4.4 28 ;
        RECT 1 31.4 4.4 59.4 ;
        RECT 4.4 0 6.4 59.4 ;
        RECT 6.4 0 9.8 28 ;
        RECT 6.4 31.4 9.8 59.4 ;
        RECT 9.8 0 10.8 59.4 ;
    LAYER V1 ;
        RECT 0 0 2 59.4 ;
        RECT 2 0 3.4 29 ;
        RECT 2 30.4 3.4 59.4 ;
        RECT 3.4 0 7.4 59.4 ;
        RECT 7.4 0 8.8 29 ;
        RECT 7.4 30.4 8.8 59.4 ;
        RECT 8.8 0 10.8 59.4 ;
  END
END INV_X1

MACRO INV_X2
  CLASS CORE ;
  FOREIGN INV_X2 0 0 ;
  ORIGIN 0 0 ;
  SIZE 10.8 BY 59.4 ;
  SITE TR1UM ;
  SYMMETRY X Y ;
  PIN VDD
    DIRECTION INOUT ;
    USE POWER ;
    PORT
      LAYER M1 ;
        RECT 0 55.7 10.8 58.3 ;
    END
  END VDD
  PIN GND
    DIRECTION INOUT ;
    USE GROUND ;
    PORT
      LAYER M1 ;
        RECT 0 1.1 10.8 3.7 ;
    END
  END GND
  PIN A
    DIRECTION INPUT ;
    USE SIGNAL ;
    PORT
      LAYER M2 ;
        RECT 1 28 4.4 31.4 ;
    END
    PORT
      LAYER M1 ;
        RECT 1 28 4.4 31.4 ;
    END
  END A
  PIN Y
    DIRECTION OUTPUT ;
    USE SIGNAL ;
    PORT
      LAYER M2 ;
        RECT 6.4 28 9.8 31.4 ;
    END
    PORT
      LAYER M1 ;
        RECT 6.4 28 9.8 31.4 ;
    END
  END Y
  OBS
    LAYER M1 ;
        RECT 0 0 1 59.4 ;
        RECT 1 0 4.4 28 ;
        RECT 1 31.4 4.4 59.4 ;
        RECT 4.4 0 6.4 59.4 ;
        RECT 6.4 0 9.8 28 ;
        RECT 6.4 31.4 9.8 59.4 ;
        RECT 9.8 0 10.8 59.4 ;
    LAYER V1 ;
        RECT 0 0 2 59.4 ;
        RECT 2 0 3.4 29 ;
        RECT 2 30.4 3.4 59.4 ;
        RECT 3.4 0 7.4 59.4 ;
        RECT 7.4 0 8.8 29 ;
        RECT 7.4 30.4 8.8 59.4 ;
        RECT 8.8 0 10.8 59.4 ;
  END
END INV_X2

MACRO MUX2
  CLASS CORE ;
  FOREIGN MUX2 0 0 ;
  ORIGIN 0 0 ;
  SIZE 32.4 BY 59.4 ;
  SITE TR1UM ;
  SYMMETRY X Y ;
  PIN VDD
    DIRECTION INOUT ;
    USE POWER ;
    PORT
      LAYER M1 ;
        RECT 0 55.7 32.4 58.3 ;
    END
  END VDD
  PIN GND
    DIRECTION INOUT ;
    USE GROUND ;
    PORT
      LAYER M1 ;
        RECT 0 1.1 32.4 3.7 ;
    END
  END GND
  PIN A
    DIRECTION INPUT ;
    USE SIGNAL ;
    PORT
      LAYER M2 ;
        RECT 1 27.9 4.4 31.3 ;
    END
    PORT
      LAYER M1 ;
        RECT 1 27.9 4.4 31.3 ;
    END
  END A
  PIN B
    DIRECTION INPUT ;
    USE SIGNAL ;
    PORT
      LAYER M2 ;
        RECT 22.6 27.9 26 31.3 ;
    END
    PORT
      LAYER M1 ;
        RECT 22.6 27.9 26 31.3 ;
    END
  END B
  PIN S
    DIRECTION INPUT ;
    USE SIGNAL ;
    PORT
      LAYER M2 ;
        RECT 17.2 6.3 20.6 9.7 ;
    END
    PORT
      LAYER M1 ;
        RECT 17.2 6.3 20.6 9.7 ;
    END
  END S
  PIN Y
    DIRECTION OUTPUT ;
    USE SIGNAL ;
    PORT
      LAYER M2 ;
        RECT 28 27.9 31.4 31.3 ;
    END
    PORT
      LAYER M1 ;
        RECT 28 27.9 31.4 31.3 ;
    END
  END Y
  OBS
    LAYER M1 ;
        RECT 0 0 1 59.4 ;
        RECT 1 0 4.4 27.9 ;
        RECT 1 31.3 4.4 59.4 ;
        RECT 4.4 0 17.2 59.4 ;
        RECT 17.2 0 20.6 6.3 ;
        RECT 17.2 9.7 20.6 59.4 ;
        RECT 20.6 0 22.6 59.4 ;
        RECT 22.6 0 26 27.9 ;
        RECT 22.6 31.3 26 59.4 ;
        RECT 26 0 28 59.4 ;
        RECT 28 0 31.4 27.9 ;
        RECT 28 31.3 31.4 59.4 ;
        RECT 31.4 0 32.4 59.4 ;
    LAYER V1 ;
        RECT 0 0 2 59.4 ;
        RECT 2 0 3.4 28.9 ;
        RECT 2 30.3 3.4 59.4 ;
        RECT 3.4 0 18.2 59.4 ;
        RECT 18.2 0 19.6 7.3 ;
        RECT 18.2 8.7 19.6 59.4 ;
        RECT 19.6 0 23.6 59.4 ;
        RECT 23.6 0 25 28.9 ;
        RECT 23.6 30.3 25 59.4 ;
        RECT 25 0 29 59.4 ;
        RECT 29 0 30.4 28.9 ;
        RECT 29 30.3 30.4 59.4 ;
        RECT 30.4 0 32.4 59.4 ;
  END
END MUX2

MACRO MUXDFFRB
  CLASS CORE ;
  FOREIGN MUXDFFRB 0 0 ;
  ORIGIN 0 0 ;
  SIZE 97.2 BY 59.4 ;
  SITE TR1UM ;
  SYMMETRY X Y ;
  PIN VDD
    DIRECTION INOUT ;
    USE POWER ;
    PORT
      LAYER M1 ;
        RECT 0 55.7 97.2 58.3 ;
    END
  END VDD
  PIN GND
    DIRECTION INOUT ;
    USE GROUND ;
    PORT
      LAYER M1 ;
        RECT 0 1.1 97.2 3.7 ;
    END
  END GND
  PIN A
    DIRECTION INPUT ;
    USE SIGNAL ;
    PORT
      LAYER M2 ;
        RECT 1 27.9 4.4 31.3 ;
    END
    PORT
      LAYER M1 ;
        RECT 1 27.9 4.4 31.3 ;
    END
  END A
  PIN B
    DIRECTION INPUT ;
    USE SIGNAL ;
    PORT
      LAYER M2 ;
        RECT 22.6 27.9 26 31.3 ;
    END
    PORT
      LAYER M1 ;
        RECT 22.6 27.9 26 31.3 ;
    END
  END B
  PIN CK
    DIRECTION INPUT ;
    USE SIGNAL ;
    PORT
      LAYER M2 ;
        RECT 33.4 27.7 36.8 31.1 ;
    END
    PORT
      LAYER M1 ;
        RECT 33.4 27.7 36.8 31.1 ;
    END
  END CK
  PIN Q
    DIRECTION OUTPUT ;
    USE SIGNAL ;
    PORT
      LAYER M2 ;
        RECT 92.8 27.9 96.2 31.3 ;
    END
    PORT
      LAYER M1 ;
        RECT 92.8 27.9 96.2 31.3 ;
    END
  END Q
  PIN QB
    DIRECTION OUTPUT ;
    USE SIGNAL ;
    PORT
      LAYER M2 ;
        RECT 82 27.9 85.4 31.3 ;
        RECT 82 27.9 85.4 31.3 ;
    END
    PORT
      LAYER M1 ;
        RECT 82 27.9 85.4 31.3 ;
        RECT 82 27.9 85.4 31.3 ;
    END
  END QB
  PIN RSTB
    DIRECTION INPUT ;
    USE SIGNAL ;
    PORT
      LAYER M2 ;
        RECT 87.4 27.9 90.8 31.3 ;
    END
    PORT
      LAYER M1 ;
        RECT 87.4 27.9 90.8 31.3 ;
    END
  END RSTB
  PIN S
    DIRECTION INPUT ;
    USE SIGNAL ;
    PORT
      LAYER M2 ;
        RECT 17.2 6.3 20.6 9.7 ;
    END
    PORT
      LAYER M1 ;
        RECT 17.2 6.3 20.6 9.7 ;
    END
  END S
  OBS
    LAYER M1 ;
        RECT 0 0 1 59.4 ;
        RECT 1 0 4.4 27.9 ;
        RECT 1 31.3 4.4 59.4 ;
        RECT 4.4 0 17.2 59.4 ;
        RECT 17.2 0 20.6 6.3 ;
        RECT 17.2 9.7 20.6 59.4 ;
        RECT 20.6 0 22.6 59.4 ;
        RECT 22.6 0 26 27.9 ;
        RECT 22.6 31.3 26 59.4 ;
        RECT 26 0 33.4 59.4 ;
        RECT 33.4 0 36.8 27.7 ;
        RECT 33.4 31.1 36.8 59.4 ;
        RECT 36.8 0 82 59.4 ;
        RECT 82 0 85.4 27.9 ;
        RECT 82 31.3 85.4 59.4 ;
        RECT 85.4 0 87.4 59.4 ;
        RECT 87.4 0 90.8 27.9 ;
        RECT 87.4 31.3 90.8 59.4 ;
        RECT 90.8 0 92.8 59.4 ;
        RECT 92.8 0 96.2 27.9 ;
        RECT 92.8 31.3 96.2 59.4 ;
        RECT 96.2 0 97.2 59.4 ;
    LAYER V1 ;
        RECT 0 0 2 59.4 ;
        RECT 2 0 3.4 28.9 ;
        RECT 2 30.3 3.4 59.4 ;
        RECT 3.4 0 18.2 59.4 ;
        RECT 18.2 0 19.6 7.3 ;
        RECT 18.2 8.7 19.6 59.4 ;
        RECT 19.6 0 23.6 59.4 ;
        RECT 23.6 0 25 28.9 ;
        RECT 23.6 30.3 25 59.4 ;
        RECT 25 0 34.4 59.4 ;
        RECT 34.4 0 35.8 28.7 ;
        RECT 34.4 30.1 35.8 59.4 ;
        RECT 35.8 0 83 59.4 ;
        RECT 83 0 84.4 28.9 ;
        RECT 83 30.3 84.4 59.4 ;
        RECT 84.4 0 88.4 59.4 ;
        RECT 88.4 0 89.8 28.9 ;
        RECT 88.4 30.3 89.8 59.4 ;
        RECT 89.8 0 93.8 59.4 ;
        RECT 93.8 0 95.2 28.9 ;
        RECT 93.8 30.3 95.2 59.4 ;
        RECT 95.2 0 97.2 59.4 ;
  END
END MUXDFFRB

MACRO NAND2
  CLASS CORE ;
  FOREIGN NAND2 0 0 ;
  ORIGIN 0 0 ;
  SIZE 16.2 BY 59.4 ;
  SITE TR1UM ;
  SYMMETRY X Y ;
  PIN VDD
    DIRECTION INOUT ;
    USE POWER ;
    PORT
      LAYER M1 ;
        RECT 0 55.7 16.2 58.3 ;
    END
  END VDD
  PIN GND
    DIRECTION INOUT ;
    USE GROUND ;
    PORT
      LAYER M1 ;
        RECT 0 1.1 16.2 3.7 ;
    END
  END GND
  PIN A
    DIRECTION INPUT ;
    USE SIGNAL ;
    PORT
      LAYER M2 ;
        RECT 1 28 4.4 31.4 ;
    END
    PORT
      LAYER M1 ;
        RECT 1 28 4.4 31.4 ;
    END
  END A
  PIN B
    DIRECTION INPUT ;
    USE SIGNAL ;
    PORT
      LAYER M2 ;
        RECT 6.4 28 9.8 31.4 ;
    END
    PORT
      LAYER M1 ;
        RECT 6.4 28 9.8 31.4 ;
    END
  END B
  PIN Y
    DIRECTION OUTPUT ;
    USE SIGNAL ;
    PORT
      LAYER M2 ;
        RECT 11.8 28 15.2 31.4 ;
    END
    PORT
      LAYER M1 ;
        RECT 11.8 28 15.2 31.4 ;
    END
  END Y
  OBS
    LAYER M1 ;
        RECT 0 0 1 59.4 ;
        RECT 1 0 4.4 28 ;
        RECT 1 31.4 4.4 59.4 ;
        RECT 4.4 0 6.4 59.4 ;
        RECT 6.4 0 9.8 28 ;
        RECT 6.4 31.4 9.8 59.4 ;
        RECT 9.8 0 11.8 59.4 ;
        RECT 11.8 0 15.2 28 ;
        RECT 11.8 31.4 15.2 59.4 ;
        RECT 15.2 0 16.2 59.4 ;
    LAYER V1 ;
        RECT 0 0 2 59.4 ;
        RECT 2 0 3.4 29 ;
        RECT 2 30.4 3.4 59.4 ;
        RECT 3.4 0 7.4 59.4 ;
        RECT 7.4 0 8.8 29 ;
        RECT 7.4 30.4 8.8 59.4 ;
        RECT 8.8 0 12.8 59.4 ;
        RECT 12.8 0 14.2 29 ;
        RECT 12.8 30.4 14.2 59.4 ;
        RECT 14.2 0 16.2 59.4 ;
  END
END NAND2

MACRO NAND3
  CLASS CORE ;
  FOREIGN NAND3 0 0 ;
  ORIGIN 0 0 ;
  SIZE 21.6 BY 59.4 ;
  SITE TR1UM ;
  SYMMETRY X Y ;
  PIN VDD
    DIRECTION INOUT ;
    USE POWER ;
    PORT
      LAYER M1 ;
        RECT 0 55.7 21.6 58.3 ;
    END
  END VDD
  PIN GND
    DIRECTION INOUT ;
    USE GROUND ;
    PORT
      LAYER M1 ;
        RECT 0 1.1 21.6 3.7 ;
    END
  END GND
  PIN A
    DIRECTION INPUT ;
    USE SIGNAL ;
    PORT
      LAYER M2 ;
        RECT 1 28 4.4 31.4 ;
    END
    PORT
      LAYER M1 ;
        RECT 1 28 4.4 31.4 ;
    END
  END A
  PIN B
    DIRECTION INPUT ;
    USE SIGNAL ;
    PORT
      LAYER M2 ;
        RECT 6.4 28 9.8 31.4 ;
    END
    PORT
      LAYER M1 ;
        RECT 6.4 28 9.8 31.4 ;
    END
  END B
  PIN C
    DIRECTION INPUT ;
    USE SIGNAL ;
    PORT
      LAYER M2 ;
        RECT 11.8 28 15.2 31.4 ;
    END
    PORT
      LAYER M1 ;
        RECT 11.8 28 15.2 31.4 ;
    END
  END C
  PIN Y
    DIRECTION OUTPUT ;
    USE SIGNAL ;
    PORT
      LAYER M2 ;
        RECT 17.2 28 20.6 31.4 ;
    END
    PORT
      LAYER M1 ;
        RECT 17.2 28 20.6 31.4 ;
    END
  END Y
  OBS
    LAYER M1 ;
        RECT 0 0 1 59.4 ;
        RECT 1 0 4.4 28 ;
        RECT 1 31.4 4.4 59.4 ;
        RECT 4.4 0 6.4 59.4 ;
        RECT 6.4 0 9.8 28 ;
        RECT 6.4 31.4 9.8 59.4 ;
        RECT 9.8 0 11.8 59.4 ;
        RECT 11.8 0 15.2 28 ;
        RECT 11.8 31.4 15.2 59.4 ;
        RECT 15.2 0 17.2 59.4 ;
        RECT 17.2 0 20.6 28 ;
        RECT 17.2 31.4 20.6 59.4 ;
        RECT 20.6 0 21.6 59.4 ;
    LAYER V1 ;
        RECT 0 0 2 59.4 ;
        RECT 2 0 3.4 29 ;
        RECT 2 30.4 3.4 59.4 ;
        RECT 3.4 0 7.4 59.4 ;
        RECT 7.4 0 8.8 29 ;
        RECT 7.4 30.4 8.8 59.4 ;
        RECT 8.8 0 12.8 59.4 ;
        RECT 12.8 0 14.2 29 ;
        RECT 12.8 30.4 14.2 59.4 ;
        RECT 14.2 0 18.2 59.4 ;
        RECT 18.2 0 19.6 29 ;
        RECT 18.2 30.4 19.6 59.4 ;
        RECT 19.6 0 21.6 59.4 ;
  END
END NAND3

MACRO NAND4
  CLASS CORE ;
  FOREIGN NAND4 0 0 ;
  ORIGIN 0 0 ;
  SIZE 27 BY 59.4 ;
  SITE TR1UM ;
  SYMMETRY X Y ;
  PIN VDD
    DIRECTION INOUT ;
    USE POWER ;
    PORT
      LAYER M1 ;
        RECT 0 55.7 27 58.3 ;
    END
  END VDD
  PIN GND
    DIRECTION INOUT ;
    USE GROUND ;
    PORT
      LAYER M1 ;
        RECT 0 1.1 27 3.7 ;
    END
  END GND
  PIN A
    DIRECTION INPUT ;
    USE SIGNAL ;
    PORT
      LAYER M2 ;
        RECT 1 28 4.4 31.4 ;
    END
    PORT
      LAYER M1 ;
        RECT 1 28 4.4 31.4 ;
    END
  END A
  PIN B
    DIRECTION INPUT ;
    USE SIGNAL ;
    PORT
      LAYER M2 ;
        RECT 6.4 28 9.8 31.4 ;
    END
    PORT
      LAYER M1 ;
        RECT 6.4 28 9.8 31.4 ;
    END
  END B
  PIN C
    DIRECTION INPUT ;
    USE SIGNAL ;
    PORT
      LAYER M2 ;
        RECT 11.8 28 15.2 31.4 ;
    END
    PORT
      LAYER M1 ;
        RECT 11.8 28 15.2 31.4 ;
    END
  END C
  PIN D
    DIRECTION INPUT ;
    USE SIGNAL ;
    PORT
      LAYER M2 ;
        RECT 17.2 28 20.6 31.4 ;
    END
    PORT
      LAYER M1 ;
        RECT 17.2 28 20.6 31.4 ;
    END
  END D
  PIN Y
    DIRECTION OUTPUT ;
    USE SIGNAL ;
    PORT
      LAYER M2 ;
        RECT 22.6 28 26 31.4 ;
    END
    PORT
      LAYER M1 ;
        RECT 22.6 28 26 31.4 ;
    END
  END Y
  OBS
    LAYER M1 ;
        RECT 0 0 1 59.4 ;
        RECT 1 0 4.4 28 ;
        RECT 1 31.4 4.4 59.4 ;
        RECT 4.4 0 6.4 59.4 ;
        RECT 6.4 0 9.8 28 ;
        RECT 6.4 31.4 9.8 59.4 ;
        RECT 9.8 0 11.8 59.4 ;
        RECT 11.8 0 15.2 28 ;
        RECT 11.8 31.4 15.2 59.4 ;
        RECT 15.2 0 17.2 59.4 ;
        RECT 17.2 0 20.6 28 ;
        RECT 17.2 31.4 20.6 59.4 ;
        RECT 20.6 0 22.6 59.4 ;
        RECT 22.6 0 26 28 ;
        RECT 22.6 31.4 26 59.4 ;
        RECT 26 0 27 59.4 ;
    LAYER V1 ;
        RECT 0 0 2 59.4 ;
        RECT 2 0 3.4 29 ;
        RECT 2 30.4 3.4 59.4 ;
        RECT 3.4 0 7.4 59.4 ;
        RECT 7.4 0 8.8 29 ;
        RECT 7.4 30.4 8.8 59.4 ;
        RECT 8.8 0 12.8 59.4 ;
        RECT 12.8 0 14.2 29 ;
        RECT 12.8 30.4 14.2 59.4 ;
        RECT 14.2 0 18.2 59.4 ;
        RECT 18.2 0 19.6 29 ;
        RECT 18.2 30.4 19.6 59.4 ;
        RECT 19.6 0 23.6 59.4 ;
        RECT 23.6 0 25 29 ;
        RECT 23.6 30.4 25 59.4 ;
        RECT 25 0 27 59.4 ;
  END
END NAND4

MACRO NOR2
  CLASS CORE ;
  FOREIGN NOR2 0 0 ;
  ORIGIN 0 0 ;
  SIZE 16.2 BY 59.4 ;
  SITE TR1UM ;
  SYMMETRY X Y ;
  PIN VDD
    DIRECTION INOUT ;
    USE POWER ;
    PORT
      LAYER M1 ;
        RECT 0 55.7 16.2 58.3 ;
    END
  END VDD
  PIN GND
    DIRECTION INOUT ;
    USE GROUND ;
    PORT
      LAYER M1 ;
        RECT 0 1.1 16.2 3.7 ;
    END
  END GND
  PIN A
    DIRECTION INPUT ;
    USE SIGNAL ;
    PORT
      LAYER M2 ;
        RECT 1 28 4.4 31.4 ;
    END
    PORT
      LAYER M1 ;
        RECT 1 28 4.4 31.4 ;
    END
  END A
  PIN B
    DIRECTION INPUT ;
    USE SIGNAL ;
    PORT
      LAYER M2 ;
        RECT 6.4 28 9.8 31.4 ;
    END
    PORT
      LAYER M1 ;
        RECT 6.4 28 9.8 31.4 ;
    END
  END B
  PIN Y
    DIRECTION OUTPUT ;
    USE SIGNAL ;
    PORT
      LAYER M2 ;
        RECT 11.8 28 15.2 31.4 ;
    END
    PORT
      LAYER M1 ;
        RECT 11.8 28 15.2 31.4 ;
    END
  END Y
  OBS
    LAYER M1 ;
        RECT 0 0 1 59.4 ;
        RECT 1 0 4.4 28 ;
        RECT 1 31.4 4.4 59.4 ;
        RECT 4.4 0 6.4 59.4 ;
        RECT 6.4 0 9.8 28 ;
        RECT 6.4 31.4 9.8 59.4 ;
        RECT 9.8 0 11.8 59.4 ;
        RECT 11.8 0 15.2 28 ;
        RECT 11.8 31.4 15.2 59.4 ;
        RECT 15.2 0 16.2 59.4 ;
    LAYER V1 ;
        RECT 0 0 2 59.4 ;
        RECT 2 0 3.4 29 ;
        RECT 2 30.4 3.4 59.4 ;
        RECT 3.4 0 7.4 59.4 ;
        RECT 7.4 0 8.8 29 ;
        RECT 7.4 30.4 8.8 59.4 ;
        RECT 8.8 0 12.8 59.4 ;
        RECT 12.8 0 14.2 29 ;
        RECT 12.8 30.4 14.2 59.4 ;
        RECT 14.2 0 16.2 59.4 ;
  END
END NOR2

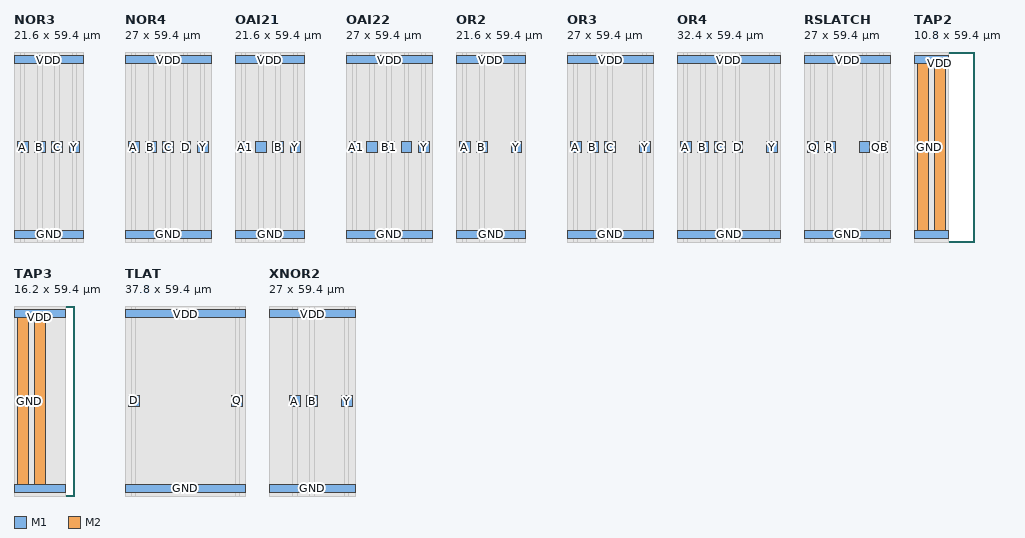
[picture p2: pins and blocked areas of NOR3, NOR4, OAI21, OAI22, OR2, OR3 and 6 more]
MACRO NOR3
  CLASS CORE ;
  FOREIGN NOR3 0 0 ;
  ORIGIN 0 0 ;
  SIZE 21.6 BY 59.4 ;
  SITE TR1UM ;
  SYMMETRY X Y ;
  PIN VDD
    DIRECTION INOUT ;
    USE POWER ;
    PORT
      LAYER M1 ;
        RECT 0 55.7 21.6 58.3 ;
    END
  END VDD
  PIN GND
    DIRECTION INOUT ;
    USE GROUND ;
    PORT
      LAYER M1 ;
        RECT 0 1.1 21.6 3.7 ;
    END
  END GND
  PIN A
    DIRECTION INPUT ;
    USE SIGNAL ;
    PORT
      LAYER M2 ;
        RECT 1 28 4.4 31.4 ;
    END
    PORT
      LAYER M1 ;
        RECT 1 28 4.4 31.4 ;
    END
  END A
  PIN B
    DIRECTION INPUT ;
    USE SIGNAL ;
    PORT
      LAYER M2 ;
        RECT 6.4 28 9.8 31.4 ;
    END
    PORT
      LAYER M1 ;
        RECT 6.4 28 9.8 31.4 ;
    END
  END B
  PIN C
    DIRECTION INPUT ;
    USE SIGNAL ;
    PORT
      LAYER M2 ;
        RECT 11.8 28 15.2 31.4 ;
    END
    PORT
      LAYER M1 ;
        RECT 11.8 28 15.2 31.4 ;
    END
  END C
  PIN Y
    DIRECTION OUTPUT ;
    USE SIGNAL ;
    PORT
      LAYER M2 ;
        RECT 17.2 28 20.6 31.4 ;
    END
    PORT
      LAYER M1 ;
        RECT 17.2 28 20.6 31.4 ;
    END
  END Y
  OBS
    LAYER M1 ;
        RECT 0 0 1 59.4 ;
        RECT 1 0 4.4 28 ;
        RECT 1 31.4 4.4 59.4 ;
        RECT 4.4 0 6.4 59.4 ;
        RECT 6.4 0 9.8 28 ;
        RECT 6.4 31.4 9.8 59.4 ;
        RECT 9.8 0 11.8 59.4 ;
        RECT 11.8 0 15.2 28 ;
        RECT 11.8 31.4 15.2 59.4 ;
        RECT 15.2 0 17.2 59.4 ;
        RECT 17.2 0 20.6 28 ;
        RECT 17.2 31.4 20.6 59.4 ;
        RECT 20.6 0 21.6 59.4 ;
    LAYER V1 ;
        RECT 0 0 2 59.4 ;
        RECT 2 0 3.4 29 ;
        RECT 2 30.4 3.4 59.4 ;
        RECT 3.4 0 7.4 59.4 ;
        RECT 7.4 0 8.8 29 ;
        RECT 7.4 30.4 8.8 59.4 ;
        RECT 8.8 0 12.8 59.4 ;
        RECT 12.8 0 14.2 29 ;
        RECT 12.8 30.4 14.2 59.4 ;
        RECT 14.2 0 18.2 59.4 ;
        RECT 18.2 0 19.6 29 ;
        RECT 18.2 30.4 19.6 59.4 ;
        RECT 19.6 0 21.6 59.4 ;
  END
END NOR3

MACRO NOR4
  CLASS CORE ;
  FOREIGN NOR4 0 0 ;
  ORIGIN 0 0 ;
  SIZE 27 BY 59.4 ;
  SITE TR1UM ;
  SYMMETRY X Y ;
  PIN VDD
    DIRECTION INOUT ;
    USE POWER ;
    PORT
      LAYER M1 ;
        RECT 0 55.7 27 58.3 ;
    END
  END VDD
  PIN GND
    DIRECTION INOUT ;
    USE GROUND ;
    PORT
      LAYER M1 ;
        RECT 0 1.1 27 3.7 ;
    END
  END GND
  PIN A
    DIRECTION INPUT ;
    USE SIGNAL ;
    PORT
      LAYER M2 ;
        RECT 1 28 4.4 31.4 ;
    END
    PORT
      LAYER M1 ;
        RECT 1 28 4.4 31.4 ;
    END
  END A
  PIN B
    DIRECTION INPUT ;
    USE SIGNAL ;
    PORT
      LAYER M2 ;
        RECT 6.4 28 9.8 31.4 ;
    END
    PORT
      LAYER M1 ;
        RECT 6.4 28 9.8 31.4 ;
    END
  END B
  PIN C
    DIRECTION INPUT ;
    USE SIGNAL ;
    PORT
      LAYER M2 ;
        RECT 11.8 28 15.2 31.4 ;
    END
    PORT
      LAYER M1 ;
        RECT 11.8 28 15.2 31.4 ;
    END
  END C
  PIN D
    DIRECTION INPUT ;
    USE SIGNAL ;
    PORT
      LAYER M2 ;
        RECT 17.2 28 20.6 31.4 ;
    END
    PORT
      LAYER M1 ;
        RECT 17.2 28 20.6 31.4 ;
    END
  END D
  PIN Y
    DIRECTION OUTPUT ;
    USE SIGNAL ;
    PORT
      LAYER M2 ;
        RECT 22.6 28 26 31.4 ;
    END
    PORT
      LAYER M1 ;
        RECT 22.6 28 26 31.4 ;
    END
  END Y
  OBS
    LAYER M1 ;
        RECT 0 0 1 59.4 ;
        RECT 1 0 4.4 28 ;
        RECT 1 31.4 4.4 59.4 ;
        RECT 4.4 0 6.4 59.4 ;
        RECT 6.4 0 9.8 28 ;
        RECT 6.4 31.4 9.8 59.4 ;
        RECT 9.8 0 11.8 59.4 ;
        RECT 11.8 0 15.2 28 ;
        RECT 11.8 31.4 15.2 59.4 ;
        RECT 15.2 0 17.2 59.4 ;
        RECT 17.2 0 20.6 28 ;
        RECT 17.2 31.4 20.6 59.4 ;
        RECT 20.6 0 22.6 59.4 ;
        RECT 22.6 0 26 28 ;
        RECT 22.6 31.4 26 59.4 ;
        RECT 26 0 27 59.4 ;
    LAYER V1 ;
        RECT 0 0 2 59.4 ;
        RECT 2 0 3.4 29 ;
        RECT 2 30.4 3.4 59.4 ;
        RECT 3.4 0 7.4 59.4 ;
        RECT 7.4 0 8.8 29 ;
        RECT 7.4 30.4 8.8 59.4 ;
        RECT 8.8 0 12.8 59.4 ;
        RECT 12.8 0 14.2 29 ;
        RECT 12.8 30.4 14.2 59.4 ;
        RECT 14.2 0 18.2 59.4 ;
        RECT 18.2 0 19.6 29 ;
        RECT 18.2 30.4 19.6 59.4 ;
        RECT 19.6 0 23.6 59.4 ;
        RECT 23.6 0 25 29 ;
        RECT 23.6 30.4 25 59.4 ;
        RECT 25 0 27 59.4 ;
  END
END NOR4

MACRO OAI21
  CLASS CORE ;
  FOREIGN OAI21 0 0 ;
  ORIGIN 0 0 ;
  SIZE 21.6 BY 59.4 ;
  SITE TR1UM ;
  SYMMETRY X Y ;
  PIN VDD
    DIRECTION INOUT ;
    USE POWER ;
    PORT
      LAYER M1 ;
        RECT 0 55.7 21.6 58.3 ;
    END
  END VDD
  PIN GND
    DIRECTION INOUT ;
    USE GROUND ;
    PORT
      LAYER M1 ;
        RECT 0 1.1 21.6 3.7 ;
    END
  END GND
  PIN A1
    DIRECTION INPUT ;
    USE SIGNAL ;
    PORT
      LAYER M2 ;
        RECT 1 28 4.4 31.4 ;
    END
    PORT
      LAYER M1 ;
        RECT 1 28 4.4 31.4 ;
    END
  END A1
  PIN A2
    DIRECTION INPUT ;
    USE SIGNAL ;
    PORT
      LAYER M2 ;
        RECT 6.4 28 9.8 31.4 ;
    END
    PORT
      LAYER M1 ;
        RECT 6.4 28 9.8 31.4 ;
    END
  END A2
  PIN B
    DIRECTION INPUT ;
    USE SIGNAL ;
    PORT
      LAYER M2 ;
        RECT 11.8 28 15.2 31.4 ;
    END
    PORT
      LAYER M1 ;
        RECT 11.8 28 15.2 31.4 ;
    END
  END B
  PIN Y
    DIRECTION OUTPUT ;
    USE SIGNAL ;
    PORT
      LAYER M2 ;
        RECT 17.2 28 20.6 31.4 ;
    END
    PORT
      LAYER M1 ;
        RECT 17.2 28 20.6 31.4 ;
    END
  END Y
  OBS
    LAYER M1 ;
        RECT 0 0 1 59.4 ;
        RECT 1 0 4.4 28 ;
        RECT 1 31.4 4.4 59.4 ;
        RECT 4.4 0 6.4 59.4 ;
        RECT 6.4 0 9.8 28 ;
        RECT 6.4 31.4 9.8 59.4 ;
        RECT 9.8 0 11.8 59.4 ;
        RECT 11.8 0 15.2 28 ;
        RECT 11.8 31.4 15.2 59.4 ;
        RECT 15.2 0 17.2 59.4 ;
        RECT 17.2 0 20.6 28 ;
        RECT 17.2 31.4 20.6 59.4 ;
        RECT 20.6 0 21.6 59.4 ;
    LAYER V1 ;
        RECT 0 0 2 59.4 ;
        RECT 2 0 3.4 29 ;
        RECT 2 30.4 3.4 59.4 ;
        RECT 3.4 0 7.4 59.4 ;
        RECT 7.4 0 8.8 29 ;
        RECT 7.4 30.4 8.8 59.4 ;
        RECT 8.8 0 12.8 59.4 ;
        RECT 12.8 0 14.2 29 ;
        RECT 12.8 30.4 14.2 59.4 ;
        RECT 14.2 0 18.2 59.4 ;
        RECT 18.2 0 19.6 29 ;
        RECT 18.2 30.4 19.6 59.4 ;
        RECT 19.6 0 21.6 59.4 ;
  END
END OAI21

MACRO OAI22
  CLASS CORE ;
  FOREIGN OAI22 0 0 ;
  ORIGIN 0 0 ;
  SIZE 27 BY 59.4 ;
  SITE TR1UM ;
  SYMMETRY X Y ;
  PIN VDD
    DIRECTION INOUT ;
    USE POWER ;
    PORT
      LAYER M1 ;
        RECT 0 55.7 27 58.3 ;
    END
  END VDD
  PIN GND
    DIRECTION INOUT ;
    USE GROUND ;
    PORT
      LAYER M1 ;
        RECT 0 1.1 27 3.7 ;
    END
  END GND
  PIN A1
    DIRECTION INPUT ;
    USE SIGNAL ;
    PORT
      LAYER M2 ;
        RECT 1 28 4.4 31.4 ;
    END
    PORT
      LAYER M1 ;
        RECT 1 28 4.4 31.4 ;
    END
  END A1
  PIN A2
    DIRECTION INPUT ;
    USE SIGNAL ;
    PORT
      LAYER M2 ;
        RECT 6.4 28 9.8 31.4 ;
    END
    PORT
      LAYER M1 ;
        RECT 6.4 28 9.8 31.4 ;
    END
  END A2
  PIN B1
    DIRECTION INPUT ;
    USE SIGNAL ;
    PORT
      LAYER M2 ;
        RECT 11.8 28 15.2 31.4 ;
    END
    PORT
      LAYER M1 ;
        RECT 11.8 28 15.2 31.4 ;
    END
  END B1
  PIN B2
    DIRECTION INPUT ;
    USE SIGNAL ;
    PORT
      LAYER M2 ;
        RECT 17.2 28 20.6 31.4 ;
    END
    PORT
      LAYER M1 ;
        RECT 17.2 28 20.6 31.4 ;
    END
  END B2
  PIN Y
    DIRECTION OUTPUT ;
    USE SIGNAL ;
    PORT
      LAYER M2 ;
        RECT 22.6 28 26 31.4 ;
    END
    PORT
      LAYER M1 ;
        RECT 22.6 28 26 31.4 ;
    END
  END Y
  OBS
    LAYER M1 ;
        RECT 0 0 1 59.4 ;
        RECT 1 0 4.4 28 ;
        RECT 1 31.4 4.4 59.4 ;
        RECT 4.4 0 6.4 59.4 ;
        RECT 6.4 0 9.8 28 ;
        RECT 6.4 31.4 9.8 59.4 ;
        RECT 9.8 0 11.8 59.4 ;
        RECT 11.8 0 15.2 28 ;
        RECT 11.8 31.4 15.2 59.4 ;
        RECT 15.2 0 17.2 59.4 ;
        RECT 17.2 0 20.6 28 ;
        RECT 17.2 31.4 20.6 59.4 ;
        RECT 20.6 0 22.6 59.4 ;
        RECT 22.6 0 26 28 ;
        RECT 22.6 31.4 26 59.4 ;
        RECT 26 0 27 59.4 ;
    LAYER V1 ;
        RECT 0 0 2 59.4 ;
        RECT 2 0 3.4 29 ;
        RECT 2 30.4 3.4 59.4 ;
        RECT 3.4 0 7.4 59.4 ;
        RECT 7.4 0 8.8 29 ;
        RECT 7.4 30.4 8.8 59.4 ;
        RECT 8.8 0 12.8 59.4 ;
        RECT 12.8 0 14.2 29 ;
        RECT 12.8 30.4 14.2 59.4 ;
        RECT 14.2 0 18.2 59.4 ;
        RECT 18.2 0 19.6 29 ;
        RECT 18.2 30.4 19.6 59.4 ;
        RECT 19.6 0 23.6 59.4 ;
        RECT 23.6 0 25 29 ;
        RECT 23.6 30.4 25 59.4 ;
        RECT 25 0 27 59.4 ;
  END
END OAI22

MACRO OR2
  CLASS CORE ;
  FOREIGN OR2 0 0 ;
  ORIGIN 0 0 ;
  SIZE 21.6 BY 59.4 ;
  SITE TR1UM ;
  SYMMETRY X Y ;
  PIN VDD
    DIRECTION INOUT ;
    USE POWER ;
    PORT
      LAYER M1 ;
        RECT 0 55.7 21.6 58.3 ;
    END
  END VDD
  PIN GND
    DIRECTION INOUT ;
    USE GROUND ;
    PORT
      LAYER M1 ;
        RECT 0 1.1 21.6 3.7 ;
    END
  END GND
  PIN A
    DIRECTION INPUT ;
    USE SIGNAL ;
    PORT
      LAYER M2 ;
        RECT 1 28 4.4 31.4 ;
    END
    PORT
      LAYER M1 ;
        RECT 1 28 4.4 31.4 ;
    END
  END A
  PIN B
    DIRECTION INPUT ;
    USE SIGNAL ;
    PORT
      LAYER M2 ;
        RECT 6.4 28 9.8 31.4 ;
    END
    PORT
      LAYER M1 ;
        RECT 6.4 28 9.8 31.4 ;
    END
  END B
  PIN Y
    DIRECTION OUTPUT ;
    USE SIGNAL ;
    PORT
      LAYER M2 ;
        RECT 17.2 28 20.6 31.4 ;
        RECT 17.2 28 20.6 31.4 ;
    END
    PORT
      LAYER M1 ;
        RECT 17.2 28 20.6 31.4 ;
        RECT 17.2 28 20.6 31.4 ;
    END
  END Y
  OBS
    LAYER M1 ;
        RECT 0 0 1 59.4 ;
        RECT 1 0 4.4 28 ;
        RECT 1 31.4 4.4 59.4 ;
        RECT 4.4 0 6.4 59.4 ;
        RECT 6.4 0 9.8 28 ;
        RECT 6.4 31.4 9.8 59.4 ;
        RECT 9.8 0 17.2 59.4 ;
        RECT 17.2 0 20.6 28 ;
        RECT 17.2 31.4 20.6 59.4 ;
        RECT 20.6 0 21.6 59.4 ;
    LAYER V1 ;
        RECT 0 0 2 59.4 ;
        RECT 2 0 3.4 29 ;
        RECT 2 30.4 3.4 59.4 ;
        RECT 3.4 0 7.4 59.4 ;
        RECT 7.4 0 8.8 29 ;
        RECT 7.4 30.4 8.8 59.4 ;
        RECT 8.8 0 18.2 59.4 ;
        RECT 18.2 0 19.6 29 ;
        RECT 18.2 30.4 19.6 59.4 ;
        RECT 19.6 0 21.6 59.4 ;
  END
END OR2

MACRO OR3
  CLASS CORE ;
  FOREIGN OR3 0 0 ;
  ORIGIN 0 0 ;
  SIZE 27 BY 59.4 ;
  SITE TR1UM ;
  SYMMETRY X Y ;
  PIN VDD
    DIRECTION INOUT ;
    USE POWER ;
    PORT
      LAYER M1 ;
        RECT 0 55.7 27 58.3 ;
    END
  END VDD
  PIN GND
    DIRECTION INOUT ;
    USE GROUND ;
    PORT
      LAYER M1 ;
        RECT 0 1.1 27 3.7 ;
    END
  END GND
  PIN A
    DIRECTION INPUT ;
    USE SIGNAL ;
    PORT
      LAYER M2 ;
        RECT 1 28 4.4 31.4 ;
    END
    PORT
      LAYER M1 ;
        RECT 1 28 4.4 31.4 ;
    END
  END A
  PIN B
    DIRECTION INPUT ;
    USE SIGNAL ;
    PORT
      LAYER M2 ;
        RECT 6.4 28 9.8 31.4 ;
    END
    PORT
      LAYER M1 ;
        RECT 6.4 28 9.8 31.4 ;
    END
  END B
  PIN C
    DIRECTION INPUT ;
    USE SIGNAL ;
    PORT
      LAYER M2 ;
        RECT 11.8 28 15.2 31.4 ;
    END
    PORT
      LAYER M1 ;
        RECT 11.8 28 15.2 31.4 ;
    END
  END C
  PIN Y
    DIRECTION OUTPUT ;
    USE SIGNAL ;
    PORT
      LAYER M2 ;
        RECT 22.6 28 26 31.4 ;
    END
    PORT
      LAYER M1 ;
        RECT 22.6 28 26 31.4 ;
    END
  END Y
  OBS
    LAYER M1 ;
        RECT 0 0 1 59.4 ;
        RECT 1 0 4.4 28 ;
        RECT 1 31.4 4.4 59.4 ;
        RECT 4.4 0 6.4 59.4 ;
        RECT 6.4 0 9.8 28 ;
        RECT 6.4 31.4 9.8 59.4 ;
        RECT 9.8 0 11.8 59.4 ;
        RECT 11.8 0 15.2 28 ;
        RECT 11.8 31.4 15.2 59.4 ;
        RECT 15.2 0 22.6 59.4 ;
        RECT 22.6 0 26 28 ;
        RECT 22.6 31.4 26 59.4 ;
        RECT 26 0 27 59.4 ;
    LAYER V1 ;
        RECT 0 0 2 59.4 ;
        RECT 2 0 3.4 29 ;
        RECT 2 30.4 3.4 59.4 ;
        RECT 3.4 0 7.4 59.4 ;
        RECT 7.4 0 8.8 29 ;
        RECT 7.4 30.4 8.8 59.4 ;
        RECT 8.8 0 12.8 59.4 ;
        RECT 12.8 0 14.2 29 ;
        RECT 12.8 30.4 14.2 59.4 ;
        RECT 14.2 0 23.6 59.4 ;
        RECT 23.6 0 25 29 ;
        RECT 23.6 30.4 25 59.4 ;
        RECT 25 0 27 59.4 ;
  END
END OR3

MACRO OR4
  CLASS CORE ;
  FOREIGN OR4 0 0 ;
  ORIGIN 0 0 ;
  SIZE 32.4 BY 59.4 ;
  SITE TR1UM ;
  SYMMETRY X Y ;
  PIN VDD
    DIRECTION INOUT ;
    USE POWER ;
    PORT
      LAYER M1 ;
        RECT 0 55.7 32.4 58.3 ;
    END
  END VDD
  PIN GND
    DIRECTION INOUT ;
    USE GROUND ;
    PORT
      LAYER M1 ;
        RECT 0 1.1 32.4 3.7 ;
    END
  END GND
  PIN A
    DIRECTION INPUT ;
    USE SIGNAL ;
    PORT
      LAYER M2 ;
        RECT 1 28 4.4 31.4 ;
    END
    PORT
      LAYER M1 ;
        RECT 1 28 4.4 31.4 ;
    END
  END A
  PIN B
    DIRECTION INPUT ;
    USE SIGNAL ;
    PORT
      LAYER M2 ;
        RECT 6.4 28 9.8 31.4 ;
    END
    PORT
      LAYER M1 ;
        RECT 6.4 28 9.8 31.4 ;
    END
  END B
  PIN C
    DIRECTION INPUT ;
    USE SIGNAL ;
    PORT
      LAYER M2 ;
        RECT 11.8 28 15.2 31.4 ;
    END
    PORT
      LAYER M1 ;
        RECT 11.8 28 15.2 31.4 ;
    END
  END C
  PIN D
    DIRECTION INPUT ;
    USE SIGNAL ;
    PORT
      LAYER M2 ;
        RECT 17.2 28 20.6 31.4 ;
    END
    PORT
      LAYER M1 ;
        RECT 17.2 28 20.6 31.4 ;
    END
  END D
  PIN Y
    DIRECTION OUTPUT ;
    USE SIGNAL ;
    PORT
      LAYER M2 ;
        RECT 28 28 31.4 31.4 ;
    END
    PORT
      LAYER M1 ;
        RECT 28 28 31.4 31.4 ;
    END
  END Y
  OBS
    LAYER M1 ;
        RECT 0 0 1 59.4 ;
        RECT 1 0 4.4 28 ;
        RECT 1 31.4 4.4 59.4 ;
        RECT 4.4 0 6.4 59.4 ;
        RECT 6.4 0 9.8 28 ;
        RECT 6.4 31.4 9.8 59.4 ;
        RECT 9.8 0 11.8 59.4 ;
        RECT 11.8 0 15.2 28 ;
        RECT 11.8 31.4 15.2 59.4 ;
        RECT 15.2 0 17.2 59.4 ;
        RECT 17.2 0 20.6 28 ;
        RECT 17.2 31.4 20.6 59.4 ;
        RECT 20.6 0 28 59.4 ;
        RECT 28 0 31.4 28 ;
        RECT 28 31.4 31.4 59.4 ;
        RECT 31.4 0 32.4 59.4 ;
    LAYER V1 ;
        RECT 0 0 2 59.4 ;
        RECT 2 0 3.4 29 ;
        RECT 2 30.4 3.4 59.4 ;
        RECT 3.4 0 7.4 59.4 ;
        RECT 7.4 0 8.8 29 ;
        RECT 7.4 30.4 8.8 59.4 ;
        RECT 8.8 0 12.8 59.4 ;
        RECT 12.8 0 14.2 29 ;
        RECT 12.8 30.4 14.2 59.4 ;
        RECT 14.2 0 18.2 59.4 ;
        RECT 18.2 0 19.6 29 ;
        RECT 18.2 30.4 19.6 59.4 ;
        RECT 19.6 0 29 59.4 ;
        RECT 29 0 30.4 29 ;
        RECT 29 30.4 30.4 59.4 ;
        RECT 30.4 0 32.4 59.4 ;
  END
END OR4

MACRO RSLATCH
  CLASS CORE ;
  FOREIGN RSLATCH 0 0 ;
  ORIGIN 0 0 ;
  SIZE 27 BY 59.4 ;
  SITE TR1UM ;
  SYMMETRY X Y ;
  PIN VDD
    DIRECTION INOUT ;
    USE POWER ;
    PORT
      LAYER M1 ;
        RECT 0 55.7 27 58.3 ;
    END
  END VDD
  PIN GND
    DIRECTION INOUT ;
    USE GROUND ;
    PORT
      LAYER M1 ;
        RECT 0 1.1 27 3.7 ;
    END
  END GND
  PIN Q
    DIRECTION OUTPUT ;
    USE SIGNAL ;
    PORT
      LAYER M2 ;
        RECT 1 28 4.4 31.4 ;
    END
    PORT
      LAYER M1 ;
        RECT 1 28 4.4 31.4 ;
    END
  END Q
  PIN QB
    DIRECTION OUTPUT ;
    USE SIGNAL ;
    PORT
      LAYER M2 ;
        RECT 22.6 28 26 31.4 ;
    END
    PORT
      LAYER M1 ;
        RECT 22.6 28 26 31.4 ;
    END
  END QB
  PIN R
    DIRECTION INPUT ;
    USE SIGNAL ;
    PORT
      LAYER M2 ;
        RECT 6.4 28 9.8 31.4 ;
    END
    PORT
      LAYER M1 ;
        RECT 6.4 28 9.8 31.4 ;
    END
  END R
  PIN S
    DIRECTION INPUT ;
    USE SIGNAL ;
    PORT
      LAYER M2 ;
        RECT 17.2 28 20.6 31.4 ;
    END
    PORT
      LAYER M1 ;
        RECT 17.2 28 20.6 31.4 ;
    END
  END S
  OBS
    LAYER M1 ;
        RECT 0 0 1 59.4 ;
        RECT 1 0 4.4 28 ;
        RECT 1 31.4 4.4 59.4 ;
        RECT 4.4 0 6.4 59.4 ;
        RECT 6.4 0 9.8 28 ;
        RECT 6.4 31.4 9.8 59.4 ;
        RECT 9.8 0 17.2 59.4 ;
        RECT 17.2 0 20.6 28 ;
        RECT 17.2 31.4 20.6 59.4 ;
        RECT 20.6 0 22.6 59.4 ;
        RECT 22.6 0 26 28 ;
        RECT 22.6 31.4 26 59.4 ;
        RECT 26 0 27 59.4 ;
    LAYER V1 ;
        RECT 0 0 2 59.4 ;
        RECT 2 0 3.4 29 ;
        RECT 2 30.4 3.4 59.4 ;
        RECT 3.4 0 7.4 59.4 ;
        RECT 7.4 0 8.8 29 ;
        RECT 7.4 30.4 8.8 59.4 ;
        RECT 8.8 0 18.2 59.4 ;
        RECT 18.2 0 19.6 29 ;
        RECT 18.2 30.4 19.6 59.4 ;
        RECT 19.6 0 23.6 59.4 ;
        RECT 23.6 0 25 29 ;
        RECT 23.6 30.4 25 59.4 ;
        RECT 25 0 27 59.4 ;
  END
END RSLATCH

MACRO TAP2
  CLASS CORE WELLTAP ;
  FOREIGN TAP2 0 0 ;
  ORIGIN 0 0 ;
  SIZE 10.8 BY 59.4 ;
  SITE TR1UM ;
  SYMMETRY X Y ;
  PIN VDD
    DIRECTION INOUT ;
    USE POWER ;
    PORT
      LAYER M1 ;
        RECT 0 55.7 10.8 58.3 ;
      LAYER M2 ;
        RECT 6.4 1.1 9.8 58.3 ;
    END
  END VDD
  PIN GND
    DIRECTION INOUT ;
    USE GROUND ;
    PORT
      LAYER M1 ;
        RECT 0 1.1 10.8 3.7 ;
      LAYER M2 ;
        RECT 1 1.1 4.4 58.3 ;
    END
  END GND
  OBS
    LAYER M1 ;
        RECT 0 0 10.8 59.4 ;
    LAYER V1 ;
        RECT 0 0 10.8 59.4 ;
  END
END TAP2

MACRO TAP3
  CLASS CORE WELLTAP ;
  FOREIGN TAP3 0 0 ;
  ORIGIN 0 0 ;
  SIZE 16.2 BY 59.4 ;
  SITE TR1UM ;
  SYMMETRY X Y ;
  PIN VDD
    DIRECTION INOUT ;
    USE POWER ;
    PORT
      LAYER M1 ;
        RECT 0 55.7 16.2 58.3 ;
      LAYER M2 ;
        RECT 6.4 1.1 9.8 58.3 ;
    END
  END VDD
  PIN GND
    DIRECTION INOUT ;
    USE GROUND ;
    PORT
      LAYER M1 ;
        RECT 0 1.1 16.2 3.7 ;
      LAYER M2 ;
        RECT 1 1.1 4.4 58.3 ;
    END
  END GND
  OBS
    LAYER M1 ;
        RECT 0 0 16.2 59.4 ;
    LAYER V1 ;
        RECT 0 0 16.2 59.4 ;
  END
END TAP3

MACRO TLAT
  CLASS BLOCK ;
  FOREIGN TLAT 0 0 ;
  ORIGIN 0 0 ;
  SIZE 37.8 BY 59.4 ;
  SITE TR1UM ;
  SYMMETRY X Y ;
  PIN VDD
    DIRECTION INOUT ;
    USE POWER ;
    PORT
      LAYER M1 ;
        RECT 0 55.7 37.8 58.3 ;
    END
  END VDD
  PIN GND
    DIRECTION INOUT ;
    USE GROUND ;
    PORT
      LAYER M1 ;
        RECT 0 1.1 37.8 3.7 ;
    END
  END GND
  PIN D
    DIRECTION INPUT ;
    USE SIGNAL ;
    PORT
      LAYER M2 ;
        RECT 1 28.1 4.4 31.5 ;
    END
    PORT
      LAYER M1 ;
        RECT 1 28.1 4.4 31.5 ;
    END
  END D
  PIN Q
    DIRECTION OUTPUT ;
    USE SIGNAL ;
    PORT
      LAYER M2 ;
        RECT 33.4 28.1 36.8 31.5 ;
    END
    PORT
      LAYER M1 ;
        RECT 33.4 28.1 36.8 31.5 ;
    END
  END Q
  PIN RD
    DIRECTION INPUT ;
    USE SIGNAL ;
    PORT
      LAYER M2 ;
    END
    PORT
      LAYER M1 ;
    END
  END RD
  PIN RDB
    DIRECTION INPUT ;
    USE SIGNAL ;
    PORT
      LAYER M2 ;
    END
    PORT
      LAYER M1 ;
    END
  END RDB
  PIN WR
    DIRECTION INPUT ;
    USE SIGNAL ;
    PORT
      LAYER M2 ;
    END
    PORT
      LAYER M1 ;
    END
  END WR
  PIN WRB
    DIRECTION INPUT ;
    USE SIGNAL ;
    PORT
      LAYER M2 ;
    END
    PORT
      LAYER M1 ;
    END
  END WRB
  OBS
    LAYER M1 ;
        RECT 0 0 1 59.4 ;
        RECT 1 0 4.4 28.1 ;
        RECT 1 31.5 4.4 59.4 ;
        RECT 4.4 0 33.4 59.4 ;
        RECT 33.4 0 36.8 28.1 ;
        RECT 33.4 31.5 36.8 59.4 ;
        RECT 36.8 0 37.8 59.4 ;
    LAYER V1 ;
        RECT 0 0 2 59.4 ;
        RECT 2 0 3.4 29.1 ;
        RECT 2 30.5 3.4 59.4 ;
        RECT 3.4 0 34.4 59.4 ;
        RECT 34.4 0 35.8 29.1 ;
        RECT 34.4 30.5 35.8 59.4 ;
        RECT 35.8 0 37.8 59.4 ;
  END
END TLAT

MACRO XNOR2
  CLASS CORE ;
  FOREIGN XNOR2 0 0 ;
  ORIGIN 0 0 ;
  SIZE 27 BY 59.4 ;
  SITE TR1UM ;
  SYMMETRY X Y ;
  PIN VDD
    DIRECTION INOUT ;
    USE POWER ;
    PORT
      LAYER M1 ;
        RECT 0 55.7 27 58.3 ;
    END
  END VDD
  PIN GND
    DIRECTION INOUT ;
    USE GROUND ;
    PORT
      LAYER M1 ;
        RECT 0 1.1 27 3.7 ;
    END
  END GND
  PIN A
    DIRECTION INPUT ;
    USE SIGNAL ;
    PORT
      LAYER M2 ;
        RECT 6.4 27.9 9.8 31.3 ;
    END
    PORT
      LAYER M1 ;
        RECT 6.4 27.9 9.8 31.3 ;
    END
  END A
  PIN B
    DIRECTION INPUT ;
    USE SIGNAL ;
    PORT
      LAYER M2 ;
        RECT 11.8 27.9 15.2 31.3 ;
    END
    PORT
      LAYER M1 ;
        RECT 11.8 27.9 15.2 31.3 ;
    END
  END B
  PIN Y
    DIRECTION OUTPUT ;
    USE SIGNAL ;
    PORT
      LAYER M2 ;
        RECT 22.6 27.9 26 31.3 ;
    END
    PORT
      LAYER M1 ;
        RECT 22.6 27.9 26 31.3 ;
    END
  END Y
  OBS
    LAYER M1 ;
        RECT 0 0 6.4 59.4 ;
        RECT 6.4 0 9.8 27.9 ;
        RECT 6.4 31.3 9.8 59.4 ;
        RECT 9.8 0 11.8 59.4 ;
        RECT 11.8 0 15.2 27.9 ;
        RECT 11.8 31.3 15.2 59.4 ;
        RECT 15.2 0 22.6 59.4 ;
        RECT 22.6 0 26 27.9 ;
        RECT 22.6 31.3 26 59.4 ;
        RECT 26 0 27 59.4 ;
    LAYER V1 ;
        RECT 0 0 7.4 59.4 ;
        RECT 7.4 0 8.8 28.9 ;
        RECT 7.4 30.3 8.8 59.4 ;
        RECT 8.8 0 12.8 59.4 ;
        RECT 12.8 0 14.2 28.9 ;
        RECT 12.8 30.3 14.2 59.4 ;
        RECT 14.2 0 23.6 59.4 ;
        RECT 23.6 0 25 28.9 ;
        RECT 23.6 30.3 25 59.4 ;
        RECT 25 0 27 59.4 ;
  END
END XNOR2

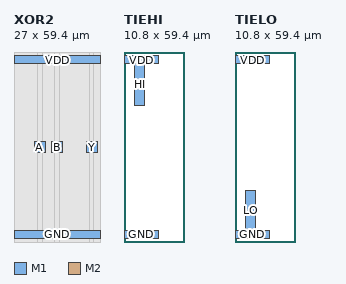
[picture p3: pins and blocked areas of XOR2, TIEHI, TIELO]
MACRO XOR2
  CLASS CORE ;
  FOREIGN XOR2 0 0 ;
  ORIGIN 0 0 ;
  SIZE 27 BY 59.4 ;
  SITE TR1UM ;
  SYMMETRY X Y ;
  PIN VDD
    DIRECTION INOUT ;
    USE POWER ;
    PORT
      LAYER M1 ;
        RECT 0 55.7 27 58.3 ;
    END
  END VDD
  PIN GND
    DIRECTION INOUT ;
    USE GROUND ;
    PORT
      LAYER M1 ;
        RECT 0 1.1 27 3.7 ;
    END
  END GND
  PIN A
    DIRECTION INPUT ;
    USE SIGNAL ;
    PORT
      LAYER M2 ;
        RECT 6.4 27.9 9.8 31.3 ;
    END
    PORT
      LAYER M1 ;
        RECT 6.4 27.9 9.8 31.3 ;
    END
  END A
  PIN B
    DIRECTION INPUT ;
    USE SIGNAL ;
    PORT
      LAYER M2 ;
        RECT 11.8 27.9 15.2 31.3 ;
    END
    PORT
      LAYER M1 ;
        RECT 11.8 27.9 15.2 31.3 ;
    END
  END B
  PIN Y
    DIRECTION OUTPUT ;
    USE SIGNAL ;
    PORT
      LAYER M2 ;
        RECT 22.6 27.9 26 31.3 ;
    END
    PORT
      LAYER M1 ;
        RECT 22.6 27.9 26 31.3 ;
    END
  END Y
  OBS
    LAYER M1 ;
        RECT 0 0 6.4 59.4 ;
        RECT 6.4 0 9.8 27.9 ;
        RECT 6.4 31.3 9.8 59.4 ;
        RECT 9.8 0 11.8 59.4 ;
        RECT 11.8 0 15.2 27.9 ;
        RECT 11.8 31.3 15.2 59.4 ;
        RECT 15.2 0 22.6 59.4 ;
        RECT 22.6 0 26 27.9 ;
        RECT 22.6 31.3 26 59.4 ;
        RECT 26 0 27 59.4 ;
    LAYER V1 ;
        RECT 0 0 7.4 59.4 ;
        RECT 7.4 0 8.8 28.9 ;
        RECT 7.4 30.3 8.8 59.4 ;
        RECT 8.8 0 12.8 59.4 ;
        RECT 12.8 0 14.2 28.9 ;
        RECT 12.8 30.3 14.2 59.4 ;
        RECT 14.2 0 23.6 59.4 ;
        RECT 23.6 0 25 28.9 ;
        RECT 23.6 30.3 25 59.4 ;
        RECT 25 0 27 59.4 ;
  END
END XOR2

MACRO TIEHI
  CLASS CORE ;
  FOREIGN TIEHI 0 0 ;
  ORIGIN 0 0 ;
  SIZE 10.8 BY 59.4 ;
  SITE TR1UM ;
  SYMMETRY X Y ;
  PIN VDD
    DIRECTION INOUT ;
    USE POWER ;
    PORT
      LAYER M1 ;
        RECT 0 55.7 10.8 58.3 ;
    END
  END VDD
  PIN GND
    DIRECTION INOUT ;
    USE GROUND ;
    PORT
      LAYER M1 ;
        RECT 0 1.1 10.8 3.7 ;
    END
  END GND
  PIN HI
    DIRECTION OUTPUT ;
    USE SIGNAL ;
    PORT
      LAYER M1 ;
        RECT 3.4 42.7 6.4 55.7 ;
    END
  END HI
  OBS
    LAYER M1 ;
        RECT 3.4 42.7 6.4 55.7 ;
  END
END TIEHI

MACRO TIELO
  CLASS CORE ;
  FOREIGN TIELO 0 0 ;
  ORIGIN 0 0 ;
  SIZE 10.8 BY 59.4 ;
  SITE TR1UM ;
  SYMMETRY X Y ;
  PIN VDD
    DIRECTION INOUT ;
    USE POWER ;
    PORT
      LAYER M1 ;
        RECT 0 55.7 10.8 58.3 ;
    END
  END VDD
  PIN GND
    DIRECTION INOUT ;
    USE GROUND ;
    PORT
      LAYER M1 ;
        RECT 0 1.1 10.8 3.7 ;
    END
  END GND
  PIN LO
    DIRECTION OUTPUT ;
    USE SIGNAL ;
    PORT
      LAYER M1 ;
        RECT 3.4 3.7 6.4 16.2 ;
    END
  END LO
  OBS
    LAYER M1 ;
        RECT 3.4 3.7 6.4 16.2 ;
  END
END TIELO

END LIBRARY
